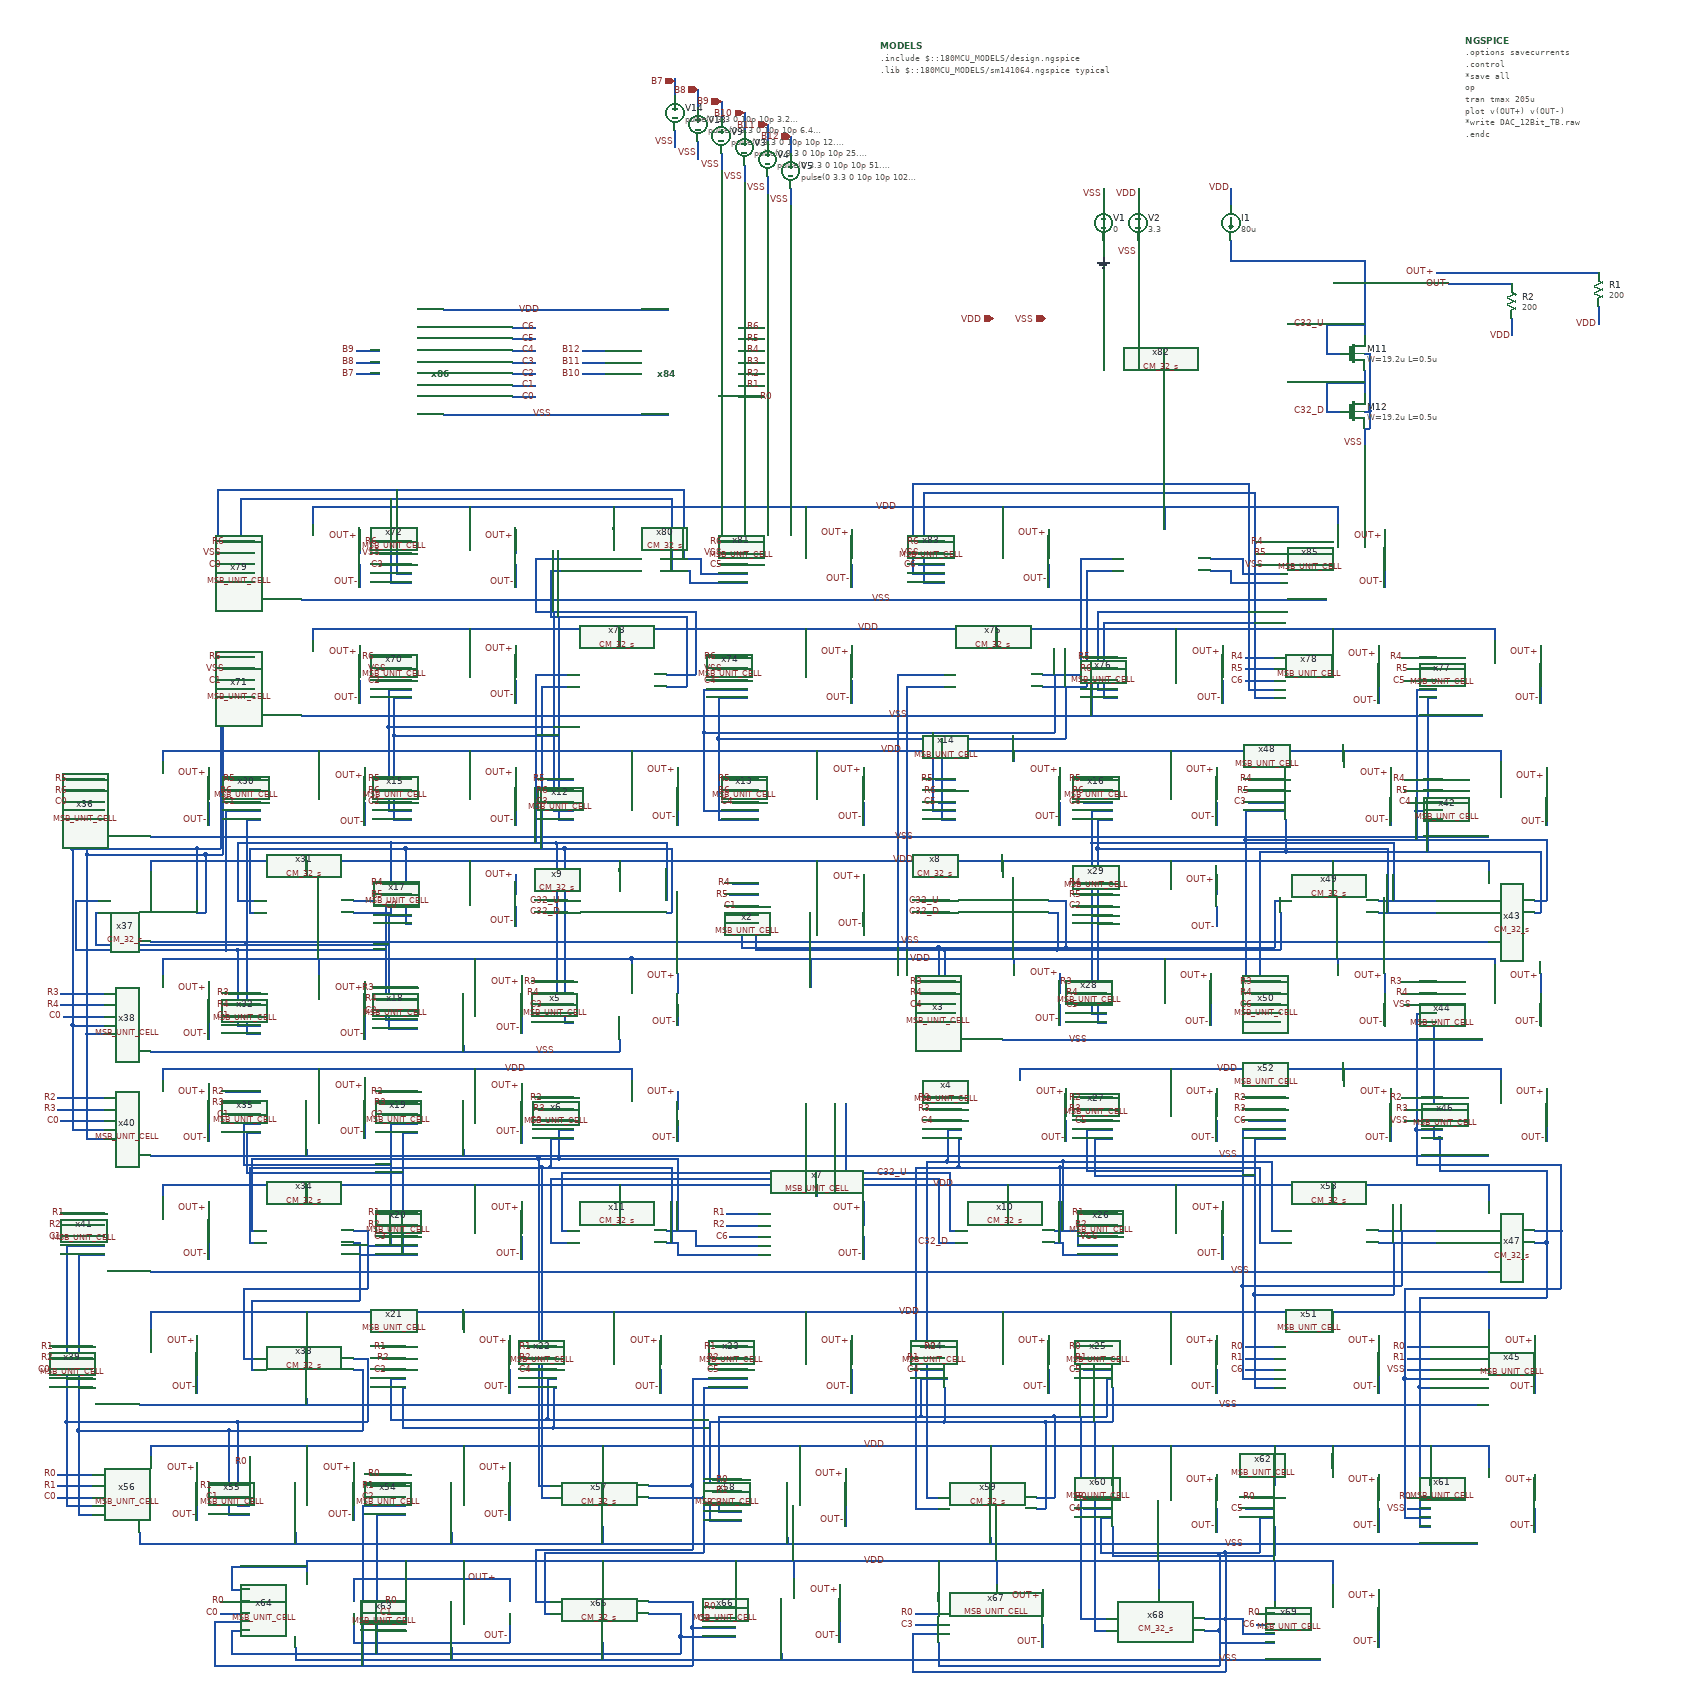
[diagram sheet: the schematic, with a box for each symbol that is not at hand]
v {xschem version=3.1.0 file_version=1.2
}
G {}
K {}
V {}
S {}
E {}
N 2280 -1190 3110 -1190 {
lab=VSS}
N 2280 -1360 3120 -1360 {
lab=VSS}
N 2280 -1540 3120 -1540 {
lab=VSS}
N 810 -1540 2280 -1540 {
lab=VSS}
N 1070 -1750 3110 -1750 {
lab=VSS}
N 1070 -1950 1900 -1950 {
lab=VSS}
N 1900 -1950 2840 -1950 {
lab=VSS}
N 1620 -1360 2280 -1360 {
lab=VSS}
N 820 -1360 1620 -1360 {
lab=VSS}
N 810 -1360 820 -1360 {
lab=VSS}
N 1060 -140 1060 -120 {
lab=VSS}
N 1060 -120 2810 -120 {
lab=VSS}
N 2810 -120 2830 -120 {
lab=VSS}
N 1330 -140 1330 -120 {
lab=VSS}
N 1590 -150 1590 -120 {
lab=VSS}
N 1900 -130 1900 -120 {
lab=VSS}
N 790 -340 790 -320 {
lab=VSS}
N 790 -320 3100 -320 {
lab=VSS}
N 1060 -340 1060 -320 {
lab=VSS}
N 1330 -340 1330 -320 {
lab=VSS}
N 1590 -350 1590 -320 {
lab=VSS}
N 1910 -330 1910 -320 {
lab=VSS}
N 2260 -330 2260 -320 {
lab=VSS}
N 790 -560 3100 -560 {
lab=VSS}
N 810 -790 3120 -790 {
lab=VSS}
N 810 -990 3120 -990 {
lab=VSS}
N 1080 -1000 1080 -990 {
lab=VSS}
N 1940 -1080 1940 -990 {
lab=VSS}
N 810 -1170 1620 -1170 {
lab=VSS}
N 1620 -1190 1620 -1170 {
lab=VSS}
N 1350 -1180 1350 -1170 {
lab=VSS}
N 1090 -2110 1090 -2080 {
lab=VDD}
N 1090 -2110 2860 -2110 {
lab=VDD}
N 2860 -2110 2860 -2080 {
lab=VDD}
N 1090 -1890 1090 -1880 {
lab=VDD}
N 1090 -1900 1090 -1890 {
lab=VDD}
N 1090 -1900 3130 -1900 {
lab=VDD}
N 3130 -1900 3130 -1880 {
lab=VDD}
N 1360 -2110 1360 -2080 {
lab=VDD}
N 1610 -2110 1610 -2070 {
lab=VDD}
N 1940 -2110 1940 -2080 {
lab=VDD}
N 2280 -2110 2280 -2080 {
lab=VDD}
N 2560 -2110 2560 -2070 {
lab=VDD}
N 2850 -1900 2850 -1880 {
lab=VDD}
N 2580 -1900 2580 -1880 {
lab=VDD}
N 2270 -1900 2270 -1870 {
lab=VDD}
N 1940 -1900 1940 -1880 {
lab=VDD}
N 1620 -1900 1620 -1870 {
lab=VDD}
N 1360 -1900 1360 -1880 {
lab=VDD}
N 830 -1690 830 -1670 {
lab=VDD}
N 830 -1690 3140 -1690 {
lab=VDD}
N 3140 -1690 3140 -1670 {
lab=VDD}
N 1100 -1690 1100 -1670 {
lab=VDD}
N 1360 -1690 1360 -1670 {
lab=VDD}
N 1640 -1690 1640 -1670 {
lab=VDD}
N 1960 -1690 1960 -1670 {
lab=VDD}
N 2300 -1690 2300 -1670 {
lab=VDD}
N 2570 -1690 2570 -1670 {
lab=VDD}
N 2870 -1690 2870 -1670 {
lab=VDD}
N 810 -1500 810 -1480 {
lab=VDD}
N 810 -1500 3120 -1500 {
lab=VDD}
N 3120 -1500 3120 -1480 {
lab=VDD}
N 2850 -1500 2850 -1480 {
lab=VDD}
N 2570 -1500 2570 -1490 {
lab=VDD}
N 1960 -1500 1960 -1490 {
lab=VDD}
N 2280 -1500 2280 -1480 {
lab=VDD}
N 1620 -1500 1620 -1480 {
lab=VDD}
N 1360 -1500 1360 -1490 {
lab=VDD}
N 1080 -1500 1080 -1480 {
lab=VDD}
N 830 -1310 830 -1300 {
lab=VDD}
N 830 -1320 830 -1310 {
lab=VDD}
N 830 -1330 830 -1320 {
lab=VDD}
N 830 -1330 1640 -1330 {
lab=VDD}
N 1640 -1330 1640 -1320 {
lab=VDD}
N 1640 -1330 3130 -1330 {
lab=VDD}
N 3130 -1330 3130 -1320 {
lab=VDD}
N 2860 -1330 2860 -1320 {
lab=VDD}
N 2560 -1330 2560 -1320 {
lab=VDD}
N 2300 -1330 2300 -1320 {
lab=VDD}
N 1350 -1000 1350 -990 {
lab=VSS}
N 830 -1140 830 -1120 {
lab=VDD}
N 830 -1140 1640 -1140 {
lab=VDD}
N 1640 -1140 1640 -1120 {
lab=VDD}
N 1370 -1140 1370 -1130 {
lab=VDD}
N 2310 -1140 2310 -1120 {
lab=VDD}
N 2310 -1140 3140 -1140 {
lab=VDD}
N 3140 -1140 3140 -1120 {
lab=VDD}
N 2570 -1140 2570 -1120 {
lab=VDD}
N 2870 -1130 2870 -1120 {
lab=VDD}
N 2870 -1140 2870 -1130 {
lab=VDD}
N 830 -940 830 -920 {
lab=VDD}
N 830 -940 3120 -940 {
lab=VDD}
N 3120 -940 3120 -910 {
lab=VDD}
N 2850 -940 2850 -910 {
lab=VDD}
N 2580 -940 2580 -920 {
lab=VDD}
N 2290 -940 2290 -910 {
lab=VDD}
N 1960 -940 1960 -920 {
lab=VDD}
N 1620 -940 1620 -910 {
lab=VDD}
N 1370 -940 1370 -920 {
lab=VDD}
N 1080 -940 1080 -910 {
lab=VDD}
N 810 -720 810 -690 {
lab=VDD}
N 810 -720 3120 -720 {
lab=VDD}
N 3120 -720 3120 -690 {
lab=VDD}
N 2850 -720 2850 -690 {
lab=VDD}
N 2570 -720 2570 -690 {
lab=VDD}
N 2280 -720 2280 -690 {
lab=VDD}
N 1940 -720 1940 -690 {
lab=VDD}
N 1610 -720 1610 -690 {
lab=VDD}
N 1350 -720 1350 -690 {
lab=VDD}
N 1080 -720 1080 -690 {
lab=VDD}
N 810 -490 810 -470 {
lab=VDD}
N 810 -490 3120 -490 {
lab=VDD}
N 3120 -490 3120 -450 {
lab=VDD}
N 1080 -290 1080 -270 {
lab=VDD}
N 1080 -290 2850 -290 {
lab=VDD}
N 2850 -290 2850 -250 {
lab=VDD}
N 2550 -290 2550 -240 {
lab=VDD}
N 2270 -290 2270 -250 {
lab=VDD}
N 1920 -290 1920 -260 {
lab=VDD}
N 1590 -290 1590 -270 {
lab=VDD}
N 1350 -290 1350 -270 {
lab=VDD}
N 1100 -1330 1100 -1300 {
lab=VDD}
N 1370 -1330 1370 -1310 {
lab=VDD}
N 1950 -1330 1950 -1280 {
lab=VDD}
N 1080 -490 1080 -470 {
lab=VDD}
N 1350 -490 1350 -470 {
lab=VDD}
N 1590 -490 1590 -470 {
lab=VDD}
N 1930 -490 1930 -460 {
lab=VDD}
N 2260 -490 2260 -450 {
lab=VDD}
N 2570 -490 2570 -450 {
lab=VDD}
N 2850 -490 2850 -450 {
lab=VDD}
N 2010 -1080 2010 -960 {
lab=C32_U}
N 2010 -960 2190 -960 {
lab=C32_U}
N 2190 -960 2190 -860 {
lab=C32_U}
N 2190 -860 2200 -860 {
lab=C32_U}
N 1990 -1080 1990 -950 {
lab=C32_D}
N 1990 -950 2170 -950 {
lab=C32_D}
N 2170 -950 2170 -840 {
lab=C32_D}
N 2170 -840 2200 -840 {
lab=C32_D}
N 1520 -960 2010 -960 {
lab=C32_U}
N 1520 -960 1520 -860 {
lab=C32_U}
N 1520 -860 1530 -860 {
lab=C32_U}
N 1500 -950 1990 -950 {
lab=C32_D}
N 1500 -950 1500 -840 {
lab=C32_D}
N 1500 -840 1530 -840 {
lab=C32_D}
N 2370 -860 2410 -860 {
lab=#net1}
N 2410 -860 2410 -835 {
lab=#net1}
N 2410 -835 2480 -835 {
lab=#net1}
N 2370 -840 2385 -840 {
lab=#net2}
N 2385 -840 2385 -820 {
lab=#net2}
N 2385 -820 2480 -820 {
lab=#net2}
N 2385 -965 2385 -860 {
lab=#net1}
N 2385 -980 2385 -965 {
lab=#net1}
N 2185 -980 2385 -980 {
lab=#net1}
N 2185 -1035 2185 -980 {
lab=#net1}
N 2185 -1035 2210 -1035 {
lab=#net1}
N 2380 -960 2380 -840 {
lab=#net2}
N 2380 -970 2380 -960 {
lab=#net2}
N 2205 -970 2380 -970 {
lab=#net2}
N 2205 -1020 2205 -970 {
lab=#net2}
N 2205 -1020 2210 -1020 {
lab=#net2}
N 2385 -980 2745 -980 {
lab=#net1}
N 2745 -980 2745 -860 {
lab=#net1}
N 2745 -860 2760 -860 {
lab=#net1}
N 2380 -970 2725 -970 {
lab=#net2}
N 2725 -970 2725 -840 {
lab=#net2}
N 2725 -840 2760 -840 {
lab=#net2}
N 2150 -980 2185 -980 {
lab=#net1}
N 2150 -980 2150 -400 {
lab=#net1}
N 2150 -400 2170 -400 {
lab=#net1}
N 2130 -970 2205 -970 {
lab=#net2}
N 2130 -970 2130 -390 {
lab=#net2}
N 2130 -390 2130 -380 {
lab=#net2}
N 2130 -380 2170 -380 {
lab=#net2}
N 1700 -860 1750 -860 {
lab=#net3}
N 1750 -860 1750 -835 {
lab=#net3}
N 1750 -835 1860 -835 {
lab=#net3}
N 1700 -840 1720 -840 {
lab=#net4}
N 1720 -840 1720 -820 {
lab=#net4}
N 1720 -820 1855 -820 {
lab=#net4}
N 1855 -820 1860 -820 {
lab=#net4}
N 1720 -985 1720 -860 {
lab=#net3}
N 1515 -985 1720 -985 {
lab=#net3}
N 1515 -1035 1515 -985 {
lab=#net3}
N 1515 -1035 1540 -1035 {
lab=#net3}
N 1710 -970 1710 -840 {
lab=#net4}
N 1500 -970 1710 -970 {
lab=#net4}
N 1500 -1020 1500 -970 {
lab=#net4}
N 1500 -1020 1540 -1020 {
lab=#net4}
N 1480 -985 1515 -985 {
lab=#net3}
N 1480 -985 1480 -420 {
lab=#net3}
N 1480 -420 1500 -420 {
lab=#net3}
N 1485 -970 1500 -970 {
lab=#net4}
N 1485 -970 1485 -400 {
lab=#net4}
N 1485 -400 1500 -400 {
lab=#net4}
N 985 -985 1480 -985 {
lab=#net3}
N 985 -985 985 -860 {
lab=#net3}
N 985 -860 990 -860 {
lab=#net3}
N 980 -970 1485 -970 {
lab=#net4}
N 980 -970 980 -840 {
lab=#net4}
N 980 -840 990 -840 {
lab=#net4}
N 2140 -1430 2190 -1430 {
lab=C32_U}
N 2140 -1410 2190 -1410 {
lab=C32_D}
N 1495 -1430 1530 -1430 {
lab=C32_U}
N 1495 -1410 1530 -1410 {
lab=C32_D}
N 2360 -1430 2390 -1430 {
lab=#net5}
N 2390 -1430 2390 -1350 {
lab=#net5}
N 2170 -1350 2390 -1350 {
lab=#net5}
N 2170 -1350 2170 -1235 {
lab=#net5}
N 2170 -1235 2200 -1235 {
lab=#net5}
N 2360 -1410 2375 -1410 {
lab=#net6}
N 2375 -1410 2375 -1345 {
lab=#net6}
N 2180 -1345 2375 -1345 {
lab=#net6}
N 2180 -1345 2180 -1220 {
lab=#net6}
N 2180 -1220 2200 -1220 {
lab=#net6}
N 1830 -1350 2170 -1350 {
lab=#net5}
N 1830 -1405 1830 -1350 {
lab=#net5}
N 1830 -1405 1860 -1405 {
lab=#net5}
N 1855 -1345 2180 -1345 {
lab=#net6}
N 1855 -1390 1855 -1345 {
lab=#net6}
N 1855 -1390 1860 -1390 {
lab=#net6}
N 2390 -1350 2750 -1350 {
lab=#net5}
N 2750 -1430 2750 -1350 {
lab=#net5}
N 2750 -1430 2760 -1430 {
lab=#net5}
N 2375 -1345 2760 -1345 {
lab=#net6}
N 2760 -1410 2760 -1345 {
lab=#net6}
N 2100 -1820 2100 -1350 {
lab=#net5}
N 2100 -1820 2180 -1820 {
lab=#net5}
N 2115 -1800 2115 -1345 {
lab=#net6}
N 2115 -1800 2180 -1800 {
lab=#net6}
N 1700 -1530 1700 -1430 {
lab=#net7}
N 1510 -1530 1700 -1530 {
lab=#net7}
N 1700 -1410 1710 -1410 {
lab=#net8}
N 1710 -1520 1710 -1410 {
lab=#net8}
N 1525 -1520 1710 -1520 {
lab=#net8}
N 1510 -1530 1510 -1235 {
lab=#net7}
N 1510 -1235 1540 -1235 {
lab=#net7}
N 1525 -1520 1525 -1220 {
lab=#net8}
N 1525 -1220 1540 -1220 {
lab=#net8}
N 1225 -1530 1510 -1530 {
lab=#net7}
N 1225 -1530 1225 -1405 {
lab=#net7}
N 1225 -1405 1260 -1405 {
lab=#net7}
N 1250 -1520 1525 -1520 {
lab=#net8}
N 1250 -1520 1250 -1390 {
lab=#net8}
N 1250 -1390 1260 -1390 {
lab=#net8}
N 960 -1530 1225 -1530 {
lab=#net7}
N 960 -1530 960 -1430 {
lab=#net7}
N 960 -1430 990 -1430 {
lab=#net7}
N 980 -1520 1250 -1520 {
lab=#net8}
N 980 -1520 980 -1410 {
lab=#net8}
N 980 -1410 990 -1410 {
lab=#net8}
N 1160 -1430 1200 -1430 {
lab=#net9}
N 1200 -1430 1205 -1430 {
lab=#net9}
N 1205 -1430 1215 -1430 {
lab=#net9}
N 1215 -1430 1215 -1225 {
lab=#net9}
N 1215 -1225 1270 -1225 {
lab=#net9}
N 1160 -1410 1220 -1410 {
lab=#net10}
N 1220 -1410 1220 -1210 {
lab=#net10}
N 1220 -1210 1270 -1210 {
lab=#net10}
N 960 -1345 1215 -1345 {
lab=#net9}
N 960 -1345 960 -1215 {
lab=#net9}
N 960 -1215 1000 -1215 {
lab=#net9}
N 975 -1355 1220 -1355 {
lab=#net10}
N 975 -1355 975 -1200 {
lab=#net10}
N 975 -1200 1000 -1200 {
lab=#net10}
N 975 -1570 975 -1355 {
lab=#net10}
N 975 -1570 1000 -1570 {
lab=#net10}
N 940 -1345 960 -1345 {
lab=#net9}
N 940 -1585 940 -1345 {
lab=#net9}
N 940 -1585 1000 -1585 {
lab=#net9}
N 715 -1355 975 -1355 {
lab=#net10}
N 715 -1410 715 -1355 {
lab=#net10}
N 715 -1410 720 -1410 {
lab=#net10}
N 680 -1345 940 -1345 {
lab=#net9}
N 680 -1430 680 -1345 {
lab=#net9}
N 680 -1430 720 -1430 {
lab=#net9}
N 1100 -1140 1100 -1130 {
lab=VDD}
N 1080 -570 1080 -560 {
lab=VSS}
N 1160 -860 1185 -860 {
lab=#net11}
N 1185 -860 1185 -760 {
lab=#net11}
N 970 -760 1185 -760 {
lab=#net11}
N 970 -760 970 -645 {
lab=#net11}
N 970 -645 970 -640 {
lab=#net11}
N 970 -640 990 -640 {
lab=#net11}
N 1160 -840 1170 -840 {
lab=#net12}
N 1170 -840 1170 -740 {
lab=#net12}
N 985 -740 1170 -740 {
lab=#net12}
N 985 -740 985 -620 {
lab=#net12}
N 985 -620 990 -620 {
lab=#net12}
N 1185 -835 1270 -835 {
lab=#net11}
N 1170 -820 1270 -820 {
lab=#net12}
N 1225 -1045 1225 -835 {
lab=#net11}
N 1225 -1045 1270 -1045 {
lab=#net11}
N 1245 -1030 1245 -820 {
lab=#net12}
N 1245 -1030 1270 -1030 {
lab=#net12}
N 970 -975 1225 -975 {
lab=#net11}
N 970 -1045 970 -975 {
lab=#net11}
N 970 -1045 1000 -1045 {
lab=#net11}
N 975 -960 1245 -960 {
lab=#net12}
N 975 -1030 975 -960 {
lab=#net12}
N 975 -1030 1000 -1030 {
lab=#net12}
N 1160 -640 1185 -640 {
lab=#net13}
N 1185 -640 1185 -530 {
lab=#net13}
N 960 -530 1185 -530 {
lab=#net13}
N 960 -530 960 -385 {
lab=#net13}
N 960 -385 980 -385 {
lab=#net13}
N 1160 -620 1175 -620 {
lab=#net14}
N 1175 -620 1175 -515 {
lab=#net14}
N 975 -515 1175 -515 {
lab=#net14}
N 945 -515 975 -515 {
lab=#net14}
N 945 -515 945 -370 {
lab=#net14}
N 945 -370 980 -370 {
lab=#net14}
N 665 -530 960 -530 {
lab=#net13}
N 665 -530 665 -385 {
lab=#net13}
N 665 -385 710 -385 {
lab=#net13}
N 685 -515 945 -515 {
lab=#net14}
N 685 -515 685 -370 {
lab=#net14}
N 685 -370 710 -370 {
lab=#net14}
N 665 -830 665 -530 {
lab=#net13}
N 665 -835 665 -830 {
lab=#net13}
N 665 -835 730 -835 {
lab=#net13}
N 685 -820 685 -515 {
lab=#net14}
N 685 -820 730 -820 {
lab=#net14}
N 665 -605 710 -605 {
lab=#net13}
N 685 -590 710 -590 {
lab=#net14}
N 1670 -420 1745 -420 {
lab=#net15}
N 1745 -605 1745 -420 {
lab=#net15}
N 1745 -605 1840 -605 {
lab=#net15}
N 1670 -400 1765 -400 {
lab=#net16}
N 1765 -590 1765 -400 {
lab=#net16}
N 1765 -590 1840 -590 {
lab=#net16}
N 1495 -535 1745 -535 {
lab=#net15}
N 1495 -605 1495 -535 {
lab=#net15}
N 1495 -605 1505 -605 {
lab=#net15}
N 1505 -520 1765 -520 {
lab=#net16}
N 1505 -590 1505 -520 {
lab=#net16}
N 1505 -590 1510 -590 {
lab=#net16}
N 1225 -535 1495 -535 {
lab=#net15}
N 1225 -605 1225 -535 {
lab=#net15}
N 1225 -605 1250 -605 {
lab=#net15}
N 1245 -520 1505 -520 {
lab=#net16}
N 1245 -590 1245 -520 {
lab=#net16}
N 1245 -590 1250 -590 {
lab=#net16}
N 1745 -420 1745 -310 {
lab=#net15}
N 1485 -220 1500 -220 {
lab=#net15}
N 1495 -200 1500 -200 {
lab=#net16}
N 1490 -200 1495 -200 {
lab=#net16}
N 1490 -305 1490 -200 {
lab=#net16}
N 1765 -400 1765 -305 {
lab=#net16}
N 1490 -305 1765 -305 {
lab=#net16}
N 1475 -310 1745 -310 {
lab=#net15}
N 1475 -310 1475 -220 {
lab=#net15}
N 1475 -220 1485 -220 {
lab=#net15}
N 2340 -400 2370 -400 {
lab=#net17}
N 2370 -540 2370 -400 {
lab=#net17}
N 2140 -540 2370 -540 {
lab=#net17}
N 2140 -605 2140 -540 {
lab=#net17}
N 2140 -605 2185 -605 {
lab=#net17}
N 2340 -380 2355 -380 {
lab=#net18}
N 2355 -530 2355 -380 {
lab=#net18}
N 2180 -530 2355 -530 {
lab=#net18}
N 2180 -590 2180 -530 {
lab=#net18}
N 2355 -530 2470 -530 {
lab=#net18}
N 2470 -590 2470 -530 {
lab=#net18}
N 2370 -540 2460 -540 {
lab=#net17}
N 2460 -605 2460 -540 {
lab=#net17}
N 2460 -605 2470 -605 {
lab=#net17}
N 1790 -540 2140 -540 {
lab=#net17}
N 1790 -540 1790 -375 {
lab=#net17}
N 1790 -375 1830 -375 {
lab=#net17}
N 1775 -530 2180 -530 {
lab=#net18}
N 1775 -530 1775 -360 {
lab=#net18}
N 1775 -360 1830 -360 {
lab=#net18}
N 2415 -540 2415 -190 {
lab=#net17}
N 2415 -190 2460 -190 {
lab=#net17}
N 2440 -530 2440 -170 {
lab=#net18}
N 2440 -170 2460 -170 {
lab=#net18}
N 2930 -860 3030 -860 {
lab=#net19}
N 2930 -840 3030 -840 {
lab=#net20}
N 2970 -860 2970 -765 {
lab=#net19}
N 2695 -765 2970 -765 {
lab=#net19}
N 2695 -765 2695 -605 {
lab=#net19}
N 2695 -605 2750 -605 {
lab=#net19}
N 2955 -840 2955 -750 {
lab=#net20}
N 2715 -750 2955 -750 {
lab=#net20}
N 2715 -750 2715 -590 {
lab=#net20}
N 2715 -590 2750 -590 {
lab=#net20}
N 2695 -1035 2695 -765 {
lab=#net19}
N 2695 -1035 2770 -1035 {
lab=#net19}
N 2715 -1020 2715 -750 {
lab=#net20}
N 2715 -1020 2770 -1020 {
lab=#net20}
N 2425 -965 2695 -965 {
lab=#net19}
N 2425 -1035 2425 -965 {
lab=#net19}
N 2425 -1035 2470 -1035 {
lab=#net19}
N 2440 -955 2715 -955 {
lab=#net20}
N 2440 -1020 2440 -955 {
lab=#net20}
N 2440 -1020 2470 -1020 {
lab=#net20}
N 2930 -1430 3030 -1430 {
lab=#net21}
N 2930 -1410 3030 -1410 {
lab=#net22}
N 2955 -1530 2955 -1430 {
lab=#net21}
N 2435 -1530 2955 -1530 {
lab=#net21}
N 2435 -1585 2435 -1530 {
lab=#net21}
N 2435 -1585 2465 -1585 {
lab=#net21}
N 2465 -1585 2470 -1585 {
lab=#net21}
N 2945 -1520 2945 -1410 {
lab=#net22}
N 2445 -1520 2945 -1520 {
lab=#net22}
N 2445 -1570 2445 -1520 {
lab=#net22}
N 2445 -1570 2470 -1570 {
lab=#net22}
N 2435 -1530 2435 -1235 {
lab=#net21}
N 2435 -1235 2460 -1235 {
lab=#net21}
N 2445 -1520 2445 -1220 {
lab=#net22}
N 2445 -1220 2460 -1220 {
lab=#net22}
N 2435 -1405 2470 -1405 {
lab=#net21}
N 2445 -1390 2470 -1390 {
lab=#net22}
N 2350 -1820 2415 -1820 {
lab=#net23}
N 2415 -2020 2415 -1820 {
lab=#net23}
N 2415 -2020 2470 -2020 {
lab=#net23}
N 2350 -1800 2425 -1800 {
lab=#net24}
N 2425 -2000 2425 -1800 {
lab=#net24}
N 2425 -2000 2470 -2000 {
lab=#net24}
N 2370 -1820 2370 -1720 {
lab=#net23}
N 1765 -1720 2370 -1720 {
lab=#net23}
N 1765 -1720 1765 -1585 {
lab=#net23}
N 1765 -1585 1860 -1585 {
lab=#net23}
N 2390 -1800 2390 -1710 {
lab=#net24}
N 1790 -1710 2390 -1710 {
lab=#net24}
N 1790 -1710 1790 -1575 {
lab=#net24}
N 1790 -1575 1790 -1570 {
lab=#net24}
N 1790 -1570 1860 -1570 {
lab=#net24}
N 2160 -1720 2160 -1585 {
lab=#net23}
N 2160 -1585 2200 -1585 {
lab=#net23}
N 2175 -1710 2175 -1570 {
lab=#net24}
N 2175 -1570 2200 -1570 {
lab=#net24}
N 1765 -1790 1765 -1720 {
lab=#net23}
N 1765 -1795 1765 -1790 {
lab=#net23}
N 1765 -1795 1840 -1795 {
lab=#net23}
N 1790 -1780 1790 -1710 {
lab=#net24}
N 1790 -1780 1840 -1780 {
lab=#net24}
N 1510 -1820 1530 -1820 {
lab=#net7}
N 1525 -1800 1530 -1800 {
lab=#net8}
N 1475 -1820 1475 -1530 {
lab=#net7}
N 1475 -1820 1510 -1820 {
lab=#net7}
N 1485 -1800 1485 -1520 {
lab=#net8}
N 1485 -1800 1525 -1800 {
lab=#net8}
N 1700 -1820 1750 -1820 {
lab=#net25}
N 1750 -1930 1750 -1820 {
lab=#net25}
N 1475 -1930 1750 -1930 {
lab=#net25}
N 1475 -2020 1475 -1930 {
lab=#net25}
N 1475 -2020 1520 -2020 {
lab=#net25}
N 1700 -1800 1735 -1800 {
lab=#net26}
N 1735 -1920 1735 -1800 {
lab=#net26}
N 1500 -1920 1735 -1920 {
lab=#net26}
N 1500 -2000 1500 -1920 {
lab=#net26}
N 1500 -2000 1520 -2000 {
lab=#net26}
N 1505 -1585 1540 -1585 {
lab=#net25}
N 1505 -1930 1505 -1585 {
lab=#net25}
N 1515 -1920 1515 -1570 {
lab=#net26}
N 1515 -1570 1540 -1570 {
lab=#net26}
N 1220 -1730 1505 -1730 {
lab=#net25}
N 1220 -1730 1220 -1585 {
lab=#net25}
N 1220 -1585 1260 -1585 {
lab=#net25}
N 1230 -1715 1515 -1715 {
lab=#net26}
N 1230 -1715 1230 -1575 {
lab=#net26}
N 1230 -1575 1230 -1570 {
lab=#net26}
N 1230 -1570 1260 -1570 {
lab=#net26}
N 1220 -1795 1220 -1730 {
lab=#net25}
N 1220 -1795 1260 -1795 {
lab=#net25}
N 1230 -1780 1260 -1780 {
lab=#net26}
N 1230 -1780 1230 -1715 {
lab=#net26}
N 890 -1520 890 -1430 {
lab=#net27}
N 675 -1520 890 -1520 {
lab=#net27}
N 675 -1585 675 -1520 {
lab=#net27}
N 675 -1585 730 -1585 {
lab=#net27}
N 890 -1410 905 -1410 {
lab=#net28}
N 905 -1510 905 -1410 {
lab=#net28}
N 700 -1510 905 -1510 {
lab=#net28}
N 700 -1570 700 -1510 {
lab=#net28}
N 700 -1570 730 -1570 {
lab=#net28}
N 675 -1520 675 -1215 {
lab=#net27}
N 675 -1215 730 -1215 {
lab=#net27}
N 700 -1510 700 -1200 {
lab=#net28}
N 700 -1200 730 -1200 {
lab=#net28}
N 890 -1520 925 -1520 {
lab=#net27}
N 925 -1520 930 -1520 {
lab=#net27}
N 930 -1790 930 -1520 {
lab=#net27}
N 930 -1795 930 -1790 {
lab=#net27}
N 930 -1795 990 -1795 {
lab=#net27}
N 905 -1510 920 -1510 {
lab=#net28}
N 920 -1510 935 -1510 {
lab=#net28}
N 935 -1780 935 -1510 {
lab=#net28}
N 935 -1780 990 -1780 {
lab=#net28}
N 700 -1200 700 -1020 {
lab=#net28}
N 700 -1020 730 -1020 {
lab=#net28}
N 675 -1215 675 -1035 {
lab=#net27}
N 675 -1035 730 -1035 {
lab=#net27}
N 1670 -220 1745 -220 {
lab=#net29}
N 1745 -220 1745 -175 {
lab=#net29}
N 1745 -175 1820 -175 {
lab=#net29}
N 1670 -200 1725 -200 {
lab=#net30}
N 1725 -200 1725 -160 {
lab=#net30}
N 1725 -160 1820 -160 {
lab=#net30}
N 1745 -175 1745 -110 {
lab=#net29}
N 925 -110 1745 -110 {
lab=#net29}
N 920 -185 980 -185 {
lab=#net29}
N 920 -185 920 -110 {
lab=#net29}
N 920 -110 925 -110 {
lab=#net29}
N 1725 -160 1725 -130 {
lab=#net30}
N 950 -130 1725 -130 {
lab=#net30}
N 950 -170 950 -130 {
lab=#net30}
N 950 -170 980 -170 {
lab=#net30}
N 1175 -385 1175 -110 {
lab=#net29}
N 1175 -385 1250 -385 {
lab=#net29}
N 1200 -370 1200 -130 {
lab=#net30}
N 1200 -370 1250 -370 {
lab=#net30}
N 1200 -170 1250 -170 {
lab=#net30}
N 1175 -185 1250 -185 {
lab=#net29}
N 2630 -190 2665 -190 {
lab=#net31}
N 2665 -305 2665 -190 {
lab=#net31}
N 2450 -305 2665 -305 {
lab=#net31}
N 2450 -365 2450 -305 {
lab=#net31}
N 2450 -365 2470 -365 {
lab=#net31}
N 2470 -350 2470 -300 {
lab=#net32}
N 2470 -300 2655 -300 {
lab=#net32}
N 2655 -300 2655 -170 {
lab=#net32}
N 2630 -170 2655 -170 {
lab=#net32}
N 2665 -190 2695 -190 {
lab=#net31}
N 2695 -190 2695 -165 {
lab=#net31}
N 2695 -165 2750 -165 {
lab=#net31}
N 2655 -170 2655 -150 {
lab=#net32}
N 2655 -150 2750 -150 {
lab=#net32}
N 2665 -305 2725 -305 {
lab=#net31}
N 2725 -365 2725 -305 {
lab=#net31}
N 2725 -365 2750 -365 {
lab=#net31}
N 2655 -300 2750 -300 {
lab=#net32}
N 2750 -350 2750 -300 {
lab=#net32}
N 2665 -190 2665 -100 {
lab=#net31}
N 2125 -100 2665 -100 {
lab=#net31}
N 2125 -165 2125 -100 {
lab=#net31}
N 2125 -165 2170 -165 {
lab=#net31}
N 2655 -170 2655 -110 {
lab=#net32}
N 2170 -110 2655 -110 {
lab=#net32}
N 2170 -150 2170 -110 {
lab=#net32}
N 3200 -860 3245 -860 {
lab=#net33}
N 3245 -860 3245 -760 {
lab=#net33}
N 2995 -760 3245 -760 {
lab=#net33}
N 2975 -760 2995 -760 {
lab=#net33}
N 2975 -760 2975 -605 {
lab=#net33}
N 2975 -605 3020 -605 {
lab=#net33}
N 3200 -840 3220 -840 {
lab=#net34}
N 3220 -840 3220 -745 {
lab=#net34}
N 3000 -745 3220 -745 {
lab=#net34}
N 3000 -745 3000 -590 {
lab=#net34}
N 3000 -590 3020 -590 {
lab=#net34}
N 2975 -605 2975 -365 {
lab=#net33}
N 2975 -365 3020 -365 {
lab=#net33}
N 3000 -590 3000 -350 {
lab=#net34}
N 3000 -350 3020 -350 {
lab=#net34}
N 3245 -975 3245 -860 {
lab=#net33}
N 2995 -975 3245 -975 {
lab=#net33}
N 2995 -1035 2995 -975 {
lab=#net33}
N 2995 -1035 3040 -1035 {
lab=#net33}
N 3220 -965 3220 -840 {
lab=#net34}
N 3035 -965 3220 -965 {
lab=#net34}
N 3035 -1020 3035 -965 {
lab=#net34}
N 3035 -1020 3040 -1020 {
lab=#net34}
N 2995 -1235 2995 -1035 {
lab=#net33}
N 2995 -1235 3030 -1235 {
lab=#net33}
N 3025 -1020 3035 -1020 {
lab=#net34}
N 3025 -1220 3025 -1020 {
lab=#net34}
N 3025 -1220 3030 -1220 {
lab=#net34}
N 3200 -1430 3220 -1430 {
lab=#net35}
N 3220 -1520 3220 -1430 {
lab=#net35}
N 3220 -1535 3220 -1520 {
lab=#net35}
N 2700 -1535 3220 -1535 {
lab=#net35}
N 2700 -1585 2700 -1535 {
lab=#net35}
N 2700 -1585 2770 -1585 {
lab=#net35}
N 3200 -1410 3210 -1410 {
lab=#net36}
N 3210 -1515 3210 -1410 {
lab=#net36}
N 2770 -1515 3210 -1515 {
lab=#net36}
N 2770 -1570 2770 -1515 {
lab=#net36}
N 2995 -1585 2995 -1535 {
lab=#net35}
N 2995 -1585 3040 -1585 {
lab=#net35}
N 3015 -1570 3015 -1515 {
lab=#net36}
N 3015 -1570 3040 -1570 {
lab=#net36}
N 2995 -1795 2995 -1585 {
lab=#net35}
N 2995 -1795 3030 -1795 {
lab=#net35}
N 3015 -1780 3015 -1570 {
lab=#net36}
N 3015 -1780 3030 -1780 {
lab=#net36}
N 2700 -1535 2700 -1235 {
lab=#net35}
N 2700 -1235 2760 -1235 {
lab=#net35}
N 2725 -1515 2770 -1515 {
lab=#net36}
N 2725 -1515 2725 -1220 {
lab=#net36}
N 2725 -1220 2760 -1220 {
lab=#net36}
N 2640 -2020 2685 -2020 {
lab=#net37}
N 2685 -2020 2695 -2020 {
lab=#net37}
N 2695 -2020 2695 -1995 {
lab=#net37}
N 2695 -1995 2760 -1995 {
lab=#net37}
N 2640 -2000 2675 -2000 {
lab=#net38}
N 2675 -2000 2675 -1980 {
lab=#net38}
N 2675 -1980 2760 -1980 {
lab=#net38}
N 2705 -1995 2705 -1795 {
lab=#net37}
N 2705 -1795 2750 -1795 {
lab=#net37}
N 2715 -1980 2715 -1780 {
lab=#net38}
N 2715 -1780 2750 -1780 {
lab=#net38}
N 2445 -1930 2705 -1930 {
lab=#net37}
N 2445 -1930 2445 -1795 {
lab=#net37}
N 2445 -1795 2480 -1795 {
lab=#net37}
N 2455 -1910 2715 -1910 {
lab=#net38}
N 2455 -1910 2455 -1780 {
lab=#net38}
N 2455 -1780 2480 -1780 {
lab=#net38}
N 2705 -2150 2705 -2000 {
lab=#net37}
N 2125 -2150 2705 -2150 {
lab=#net37}
N 2125 -2150 2125 -1995 {
lab=#net37}
N 2125 -1995 2180 -1995 {
lab=#net37}
N 2715 -2135 2715 -1980 {
lab=#net38}
N 2145 -2135 2715 -2135 {
lab=#net38}
N 2145 -2135 2145 -1980 {
lab=#net38}
N 2145 -1980 2180 -1980 {
lab=#net38}
N 1690 -2020 1760 -2020 {
lab=#net39}
N 1760 -2020 1760 -1995 {
lab=#net39}
N 1760 -1995 1840 -1995 {
lab=#net39}
N 1690 -2000 1740 -2000 {
lab=#net40}
N 1740 -2000 1740 -1980 {
lab=#net40}
N 1740 -1980 1840 -1980 {
lab=#net40}
N 1730 -2140 1730 -2020 {
lab=#net39}
N 955 -2140 1730 -2140 {
lab=#net39}
N 925 -2140 955 -2140 {
lab=#net39}
N 925 -2140 925 -1995 {
lab=#net39}
N 925 -1995 990 -1995 {
lab=#net39}
N 1710 -2125 1710 -2000 {
lab=#net40}
N 965 -2125 1710 -2125 {
lab=#net40}
N 965 -2125 965 -1980 {
lab=#net40}
N 965 -1980 990 -1980 {
lab=#net40}
N 1235 -1995 1260 -1995 {
lab=#net39}
N 1235 -2140 1235 -1995 {
lab=#net39}
N 1225 -2125 1225 -1980 {
lab=#net40}
N 1225 -1980 1260 -1980 {
lab=#net40}
N 950 -240 980 -240 {
lab=VDD}
N 950 -280 950 -240 {
lab=VDD}
N 950 -280 1080 -280 {
lab=VDD}
N 1250 -290 1250 -240 {
lab=VDD}
N 1820 -290 1820 -230 {
lab=VDD}
N 2170 -290 2170 -220 {
lab=VDD}
N 2750 -290 2750 -220 {
lab=VDD}
N 3020 -490 3020 -420 {
lab=VDD}
N 2750 -490 2750 -420 {
lab=VDD}
N 2470 -490 2470 -420 {
lab=VDD}
N 930 -220 980 -220 {
lab=R0}
N 1220 -220 1250 -220 {
lab=R0}
N 2720 -200 2750 -200 {
lab=R0}
N 2990 -400 3020 -400 {
lab=R0}
N 2980 -400 2990 -400 {
lab=R0}
N 2710 -400 2750 -400 {
lab=R0}
N 2420 -400 2470 -400 {
lab=R0}
N 650 -440 710 -440 {
lab=R0}
N 1190 -440 1250 -440 {
lab=R0}
N 1780 -430 1830 -430 {
lab=R0}
N 2140 -660 2180 -660 {
lab=R0}
N 2420 -660 2470 -660 {
lab=R0}
N 2700 -660 2750 -660 {
lab=R0}
N 2980 -660 3020 -660 {
lab=R0}
N 2980 -640 3020 -640 {
lab=R1}
N 2700 -640 2750 -640 {
lab=R1}
N 2420 -640 2470 -640 {
lab=R1}
N 2140 -640 2180 -640 {
lab=R1}
N 650 -420 710 -420 {
lab=R1}
N 920 -420 980 -420 {
lab=R1}
N 1190 -420 1250 -420 {
lab=R1}
N 1780 -410 1830 -410 {
lab=R1}
N 930 -200 980 -200 {
lab=C0}
N 1220 -200 1250 -200 {
lab=C1}
N 1780 -190 1820 -190 {
lab=C2}
N 2130 -180 2170 -180 {
lab=C3}
N 2720 -180 2750 -180 {
lab=C6}
N 2420 -380 2470 -380 {
lab=C4}
N 2700 -380 2750 -380 {
lab=C5}
N 2980 -380 3020 -380 {
lab=VSS}
N 650 -400 710 -400 {
lab=C0}
N 920 -400 980 -400 {
lab=C1}
N 1200 -400 1250 -400 {
lab=C2}
N 1780 -390 1830 -390 {
lab=C3}
N 2140 -620 2180 -620 {
lab=C4}
N 2420 -620 2470 -620 {
lab=C5}
N 2700 -620 2750 -620 {
lab=C6}
N 2980 -620 3020 -620 {
lab=VSS}
N 640 -660 710 -660 {
lab=R1}
N 640 -640 710 -640 {
lab=R2}
N 640 -620 710 -620 {
lab=C0}
N 1210 -660 1250 -660 {
lab=R1}
N 1210 -640 1250 -640 {
lab=R2}
N 1210 -620 1250 -620 {
lab=C2}
N 1460 -660 1510 -660 {
lab=R1}
N 1460 -640 1510 -640 {
lab=R2}
N 1460 -620 1510 -620 {
lab=C4}
N 1505 -605 1510 -605 {
lab=#net15}
N 1785 -660 1840 -660 {
lab=R1}
N 1790 -640 1840 -640 {
lab=R2}
N 1790 -620 1840 -620 {
lab=C5}
N 660 -890 730 -890 {
lab=R1}
N 660 -870 730 -870 {
lab=R2}
N 660 -850 730 -850 {
lab=C1}
N 1205 -890 1270 -890 {
lab=R1}
N 1205 -870 1270 -870 {
lab=R2}
N 1205 -850 1270 -850 {
lab=C3}
N 1805 -890 1860 -890 {
lab=R1}
N 1805 -870 1860 -870 {
lab=R2}
N 1810 -850 1860 -850 {
lab=C6}
N 2420 -890 2480 -890 {
lab=R1}
N 2425 -870 2480 -870 {
lab=R2}
N 2425 -850 2480 -850 {
lab=VSS}
N 650 -1090 730 -1090 {
lab=R2}
N 650 -1070 730 -1070 {
lab=R3}
N 655 -1050 730 -1050 {
lab=C0}
N 940 -1100 1000 -1100 {
lab=R2}
N 940 -1080 1000 -1080 {
lab=R3}
N 945 -1060 1000 -1060 {
lab=C1}
N 1205 -1100 1270 -1100 {
lab=R2}
N 1205 -1080 1270 -1080 {
lab=R3}
N 1210 -1060 1270 -1060 {
lab=C2}
N 1480 -1090 1540 -1090 {
lab=R2}
N 1480 -1070 1540 -1070 {
lab=R3}
N 1485 -1050 1540 -1050 {
lab=C3}
N 2155 -1090 2210 -1090 {
lab=R2}
N 2155 -1070 2210 -1070 {
lab=R3}
N 2160 -1050 2210 -1050 {
lab=C4}
N 2415 -1090 2470 -1090 {
lab=R2}
N 2415 -1070 2470 -1070 {
lab=R3}
N 2415 -1050 2470 -1050 {
lab=C5}
N 2700 -1090 2770 -1090 {
lab=R2}
N 2700 -1070 2770 -1070 {
lab=R3}
N 2705 -1050 2770 -1050 {
lab=C6}
N 2970 -1090 3040 -1090 {
lab=R2}
N 2975 -1070 3040 -1070 {
lab=R3}
N 2975 -1050 3040 -1050 {
lab=VSS}
N 655 -1270 730 -1270 {
lab=R3}
N 655 -1250 730 -1250 {
lab=R4}
N 660 -1230 730 -1230 {
lab=C0}
N 945 -1270 1000 -1270 {
lab=R3}
N 945 -1250 1000 -1250 {
lab=R4}
N 945 -1230 1000 -1230 {
lab=C1}
N 1195 -1280 1270 -1280 {
lab=R3}
N 1200 -1260 1270 -1260 {
lab=R4}
N 1200 -1240 1270 -1240 {
lab=C2}
N 1475 -1290 1540 -1290 {
lab=R3}
N 1480 -1270 1540 -1270 {
lab=R4}
N 1480 -1250 1540 -1250 {
lab=C3}
N 2140 -1290 2200 -1290 {
lab=R3}
N 2140 -1270 2200 -1270 {
lab=R4}
N 2145 -1250 2200 -1250 {
lab=C4}
N 2400 -1290 2460 -1290 {
lab=R3}
N 2405 -1270 2460 -1270 {
lab=R4}
N 2405 -1250 2460 -1250 {
lab=C5}
N 2710 -1290 2760 -1290 {
lab=R3}
N 2710 -1270 2760 -1270 {
lab=R4}
N 2710 -1250 2760 -1250 {
lab=C6}
N 2970 -1290 3030 -1290 {
lab=R3}
N 2970 -1270 3030 -1270 {
lab=R4}
N 2975 -1250 3030 -1250 {
lab=VSS}
N 1210 -1460 1260 -1460 {
lab=R4}
N 1210 -1440 1260 -1440 {
lab=R5}
N 1220 -1420 1260 -1420 {
lab=C0}
N 1815 -1460 1860 -1460 {
lab=R4}
N 1810 -1440 1860 -1440 {
lab=R5}
N 1820 -1420 1860 -1420 {
lab=C1}
N 2415 -1460 2470 -1460 {
lab=R4}
N 2415 -1440 2470 -1440 {
lab=R5}
N 2415 -1420 2470 -1420 {
lab=C2}
N 2705 -1640 2770 -1640 {
lab=R4}
N 2705 -1620 2770 -1620 {
lab=R5}
N 2705 -1600 2770 -1600 {
lab=C3}
N 2975 -1640 3040 -1640 {
lab=R4}
N 2975 -1620 3040 -1620 {
lab=R5}
N 2980 -1600 3040 -1600 {
lab=C4}
N 2700 -1850 2750 -1850 {
lab=R4}
N 2700 -1830 2750 -1830 {
lab=R5}
N 2700 -1810 2750 -1810 {
lab=C6}
N 2970 -1850 3030 -1850 {
lab=R4}
N 2980 -1830 3030 -1830 {
lab=R5}
N 2975 -1810 3030 -1810 {
lab=C5}
N 2720 -2050 2760 -2050 {
lab=R4}
N 2720 -2030 2760 -2030 {
lab=R5}
N 2720 -2010 2760 -2010 {
lab=VSS}
N 665 -1640 730 -1640 {
lab=R5}
N 665 -1620 730 -1620 {
lab=R6}
N 670 -1600 730 -1600 {
lab=C0}
N 950 -1640 1000 -1640 {
lab=R5}
N 950 -1620 1000 -1620 {
lab=R6}
N 950 -1600 1000 -1600 {
lab=C1}
N 1210 -1640 1260 -1640 {
lab=R5}
N 1205 -1620 1260 -1620 {
lab=R6}
N 1205 -1600 1260 -1600 {
lab=C2}
N 1495 -1640 1540 -1640 {
lab=R5}
N 1495 -1620 1540 -1620 {
lab=R6}
N 1495 -1600 1540 -1600 {
lab=C3}
N 1810 -1640 1860 -1640 {
lab=R5}
N 1810 -1620 1860 -1620 {
lab=R6}
N 1815 -1600 1860 -1600 {
lab=C4}
N 2165 -1640 2200 -1640 {
lab=R5}
N 2165 -1620 2200 -1620 {
lab=R6}
N 2170 -1600 2200 -1600 {
lab=C5}
N 2415 -1640 2470 -1640 {
lab=R5}
N 2420 -1620 2470 -1620 {
lab=R6}
N 2420 -1600 2470 -1600 {
lab=C6}
N 2430 -1850 2480 -1850 {
lab=R5}
N 2435 -1830 2480 -1830 {
lab=R6}
N 2435 -1810 2480 -1810 {
lab=VSS}
N 2435 -1810 2435 -1750 {
lab=VSS}
N 935 -1850 990 -1850 {
lab=R6}
N 935 -1830 990 -1830 {
lab=VSS}
N 935 -1810 990 -1810 {
lab=C1}
N 1200 -1850 1260 -1850 {
lab=R6}
N 1200 -1830 1260 -1830 {
lab=VSS}
N 1200 -1810 1260 -1810 {
lab=C2}
N 1780 -1850 1840 -1850 {
lab=R6}
N 1780 -1830 1840 -1830 {
lab=VSS}
N 1780 -1810 1840 -1810 {
lab=C4}
N 935 -2050 990 -2050 {
lab=R6}
N 935 -2030 990 -2030 {
lab=VSS}
N 935 -2010 990 -2010 {
lab=C0}
N 1200 -2050 1260 -2050 {
lab=R6}
N 1205 -2030 1260 -2030 {
lab=VSS}
N 1205 -2010 1260 -2010 {
lab=C3}
N 1795 -2050 1840 -2050 {
lab=R6}
N 1795 -2030 1840 -2030 {
lab=VSS}
N 1795 -2010 1840 -2010 {
lab=C5}
N 2135 -2050 2180 -2050 {
lab=R6}
N 2135 -2030 2180 -2030 {
lab=VSS}
N 2135 -2010 2180 -2010 {
lab=C6}
N 1720 -1305 1720 -1270 {
lab=OUT+}
N 1720 -1250 1720 -1215 {
lab=OUT-}
N 1720 -1100 1720 -1070 {
lab=OUT+}
N 1720 -1050 1720 -1015 {
lab=OUT-}
N 1450 -1300 1450 -1260 {
lab=OUT+}
N 1450 -1240 1450 -1200 {
lab=OUT-}
N 1450 -1115 1450 -1080 {
lab=OUT+}
N 1450 -1060 1450 -1035 {
lab=OUT-}
N 1180 -1125 1180 -1080 {
lab=OUT+}
N 1180 -1060 1180 -1020 {
lab=OUT-}
N 910 -1115 910 -1070 {
lab=OUT+}
N 910 -1050 910 -1015 {
lab=OUT-}
N 910 -910 910 -870 {
lab=OUT+}
N 910 -850 910 -810 {
lab=OUT-}
N 1450 -910 1450 -870 {
lab=OUT+}
N 1450 -850 1450 -810 {
lab=OUT-}
N 2040 -910 2040 -870 {
lab=OUT+}
N 2040 -850 2040 -810 {
lab=OUT-}
N 2660 -910 2660 -870 {
lab=OUT+}
N 2660 -850 2660 -810 {
lab=OUT-}
N 3200 -680 3200 -640 {
lab=OUT+}
N 3200 -620 3200 -580 {
lab=OUT-}
N 2930 -680 2930 -640 {
lab=OUT+}
N 2930 -620 2930 -580 {
lab=OUT-}
N 2650 -680 2650 -640 {
lab=OUT+}
N 2650 -620 2650 -580 {
lab=OUT-}
N 2360 -680 2360 -640 {
lab=OUT+}
N 2360 -620 2360 -580 {
lab=OUT-}
N 2020 -680 2020 -640 {
lab=OUT+}
N 2020 -620 2020 -580 {
lab=OUT-}
N 1690 -680 1690 -640 {
lab=OUT+}
N 1690 -620 1690 -580 {
lab=OUT-}
N 1430 -680 1430 -640 {
lab=OUT+}
N 1430 -620 1430 -580 {
lab=OUT-}
N 890 -680 890 -640 {
lab=OUT+}
N 890 -620 890 -580 {
lab=OUT-}
N 890 -460 890 -420 {
lab=OUT+}
N 890 -400 890 -360 {
lab=OUT-}
N 1160 -460 1160 -420 {
lab=OUT+}
N 1160 -400 1160 -360 {
lab=OUT-}
N 1430 -460 1430 -420 {
lab=OUT+}
N 1430 -400 1430 -360 {
lab=OUT-}
N 2010 -450 2010 -410 {
lab=OUT+}
N 2010 -390 2010 -350 {
lab=OUT-}
N 2650 -440 2650 -400 {
lab=OUT+}
N 2650 -380 2650 -340 {
lab=OUT-}
N 2930 -440 2930 -400 {
lab=OUT+}
N 2930 -380 2930 -340 {
lab=OUT-}
N 3200 -440 3200 -400 {
lab=OUT+}
N 3200 -380 3200 -340 {
lab=OUT-}
N 1160 -260 1160 -220 {
lab=OUT+}
N 1160 -200 1160 -160 {
lab=OUT-}
N 1430 -260 1430 -220 {
lab=OUT+}
N 1430 -200 1430 -160 {
lab=OUT-}
N 2000 -250 2000 -210 {
lab=OUT+}
N 2000 -190 2000 -150 {
lab=OUT-}
N 2350 -240 2350 -200 {
lab=OUT+}
N 2350 -180 2350 -140 {
lab=OUT-}
N 2930 -240 2930 -200 {
lab=OUT+}
N 2930 -180 2930 -140 {
lab=OUT-}
N 1170 -2070 1170 -2030 {
lab=OUT+}
N 1170 -2010 1170 -1970 {
lab=OUT-}
N 1440 -2070 1440 -2030 {
lab=OUT+}
N 1440 -2010 1440 -1970 {
lab=OUT-}
N 2020 -2070 2020 -2030 {
lab=OUT+}
N 2020 -2010 2020 -1970 {
lab=OUT-}
N 2360 -2070 2360 -2030 {
lab=OUT+}
N 2360 -2010 2360 -1970 {
lab=OUT-}
N 2940 -2070 2940 -2030 {
lab=OUT+}
N 2940 -2010 2940 -1970 {
lab=OUT-}
N 3210 -1870 3210 -1830 {
lab=OUT+}
N 3210 -1810 3210 -1770 {
lab=OUT-}
N 2930 -1870 2930 -1830 {
lab=OUT+}
N 2930 -1810 2930 -1770 {
lab=OUT-}
N 2660 -1870 2660 -1830 {
lab=OUT+}
N 2660 -1810 2660 -1770 {
lab=OUT-}
N 2020 -1870 2020 -1830 {
lab=OUT+}
N 2020 -1810 2020 -1770 {
lab=OUT-}
N 1440 -1870 1440 -1830 {
lab=OUT+}
N 1440 -1810 1440 -1770 {
lab=OUT-}
N 1170 -1870 1170 -1830 {
lab=OUT+}
N 1170 -1810 1170 -1770 {
lab=OUT-}
N 910 -1660 910 -1620 {
lab=OUT+}
N 910 -1600 910 -1560 {
lab=OUT-}
N 1180 -1660 1180 -1620 {
lab=OUT+}
N 1180 -1600 1180 -1560 {
lab=OUT-}
N 1440 -1660 1440 -1620 {
lab=OUT+}
N 1440 -1600 1440 -1560 {
lab=OUT-}
N 1720 -1660 1720 -1620 {
lab=OUT+}
N 1720 -1600 1720 -1560 {
lab=OUT-}
N 2040 -1660 2040 -1620 {
lab=OUT+}
N 2040 -1600 2040 -1560 {
lab=OUT-}
N 2380 -1660 2380 -1620 {
lab=OUT+}
N 2380 -1600 2380 -1560 {
lab=OUT-}
N 2650 -1660 2650 -1620 {
lab=OUT+}
N 2650 -1600 2650 -1560 {
lab=OUT-}
N 2950 -1660 2950 -1620 {
lab=OUT+}
N 2950 -1600 2950 -1560 {
lab=OUT-}
N 3220 -1660 3220 -1620 {
lab=OUT+}
N 3220 -1600 3220 -1560 {
lab=OUT-}
N 910 -1290 910 -1250 {
lab=OUT+}
N 910 -1230 910 -1190 {
lab=OUT-}
N 1180 -1290 1180 -1250 {
lab=OUT+}
N 1180 -1230 1180 -1190 {
lab=OUT-}
N 2640 -1305 2640 -1270 {
lab=OUT+}
N 2640 -1250 2640 -1215 {
lab=OUT-}
N 2940 -1305 2940 -1270 {
lab=OUT+}
N 2940 -1250 2940 -1215 {
lab=OUT-}
N 3210 -1305 3210 -1270 {
lab=OUT+}
N 3210 -1250 3210 -1215 {
lab=OUT-}
N 1440 -1475 1440 -1440 {
lab=OUT+}
N 1440 -1420 1440 -1385 {
lab=OUT-}
N 2040 -1475 2040 -1440 {
lab=OUT+}
N 2040 -1420 2040 -1385 {
lab=OUT-}
N 2650 -1475 2650 -1440 {
lab=OUT+}
N 2650 -1420 2650 -1385 {
lab=OUT-}
N 2130 -200 2170 -200 {
lab=R0}
N 1785 -210 1820 -210 {
lab=R0}
N 1315 -2450 1705 -2450 {
lab=VDD}
N 1315 -2270 1705 -2270 {
lab=VSS}
N 1165 -2380 1205 -2380 {
lab=B9}
N 1165 -2360 1205 -2360 {
lab=B8}
N 1165 -2340 1205 -2340 {
lab=B7}
N 1555 -2380 1595 -2380 {
lab=B12}
N 1555 -2360 1595 -2360 {
lab=B11}
N 1555 -2340 1595 -2340 {
lab=B10}
N 1435 -2420 1475 -2420 {
lab=C6}
N 1435 -2400 1475 -2400 {
lab=C5}
N 1435 -2380 1445 -2380 {
lab=C4}
N 1445 -2380 1475 -2380 {
lab=C4}
N 1435 -2360 1475 -2360 {
lab=C3}
N 1435 -2340 1475 -2340 {
lab=C2}
N 1435 -2300 1475 -2300 {
lab=C0}
N 1825 -2420 1865 -2420 {
lab=R6}
N 1825 -2400 1865 -2400 {
lab=R5}
N 1825 -2380 1835 -2380 {
lab=R4}
N 1835 -2380 1865 -2380 {
lab=R4}
N 1825 -2360 1865 -2360 {
lab=R3}
N 1825 -2340 1865 -2340 {
lab=R2}
N 1825 -2320 1865 -2320 {
lab=R1}
N 1435 -2320 1475 -2320 {
lab=C1}
N 1825 -2300 1865 -2300 {
lab=R0}
N 980 -470 980 -440 {
lab=R0}
N 2380 -1305 2380 -1270 {
lab=OUT+}
N 2380 -1250 2380 -1215 {
lab=OUT-}
N 2390 -1105 2390 -1070 {
lab=OUT+}
N 2390 -1050 2390 -1015 {
lab=OUT-}
N 2650 -1105 2650 -1070 {
lab=OUT+}
N 2650 -1050 2650 -1015 {
lab=OUT-}
N 2950 -1105 2950 -1070 {
lab=OUT+}
N 2950 -1050 2950 -1015 {
lab=OUT-}
N 3220 -1105 3220 -1070 {
lab=OUT+}
N 3220 -1050 3220 -1015 {
lab=OUT-}
N 1160 -260 1430 -260 {
lab=OUT+}
N 1160 -160 1160 -150 {
lab=OUT-}
N 1160 -150 1430 -150 {
lab=OUT-}
N 1430 -160 1430 -150 {
lab=OUT-}
N 1450 -1030 1450 -1010 {
lab=OUT-}
N 1450 -1035 1450 -1030 {
lab=OUT-}
N 2905 -2345 2905 -2305 {
lab=C32_D}
N 2905 -2375 2915 -2375 {
lab=VSS}
N 2915 -2375 2915 -2275 {
lab=VSS}
N 2905 -2275 2915 -2275 {
lab=VSS}
N 2905 -2275 2915 -2275 {
lab=VSS}
N 2915 -2275 2915 -2245 {
lab=VSS}
N 2905 -2245 2915 -2245 {
lab=VSS}
N 2905 -2245 2905 -2215 {
lab=VSS}
N 2840 -2375 2865 -2375 {
lab=C32_U}
N 2840 -2425 2840 -2375 {
lab=C32_U}
N 2840 -2325 2905 -2325 {
lab=C32_D}
N 2840 -2325 2840 -2275 {
lab=C32_D}
N 2840 -2275 2865 -2275 {
lab=C32_D}
N 2840 -2425 2905 -2425 {
lab=C32_U}
N 2905 -2485 2905 -2405 {
lab=C32_U}
N 2455 -2570 2455 -2540 {
lab=GND}
N 2455 -2660 2455 -2630 {
lab=VSS}
N 2515 -2660 2515 -2630 {
lab=VDD}
N 2515 -2570 2515 -2540 {
lab=VSS}
N 2675 -2660 2675 -2630 {
lab=VDD}
N 2675 -2570 2675 -2540 {
lab=C32_U}
N 1835 -2790 1835 -2760 {
lab=B10}
N 1835 -2700 1835 -2670 {
lab=VSS}
N 1875 -2770 1875 -2740 {
lab=B11}
N 1875 -2680 1875 -2650 {
lab=VSS}
N 1915 -2750 1915 -2720 {
lab=B12}
N 1915 -2660 1915 -2630 {
lab=VSS}
N 1795 -2810 1795 -2780 {
lab=B9}
N 1795 -2720 1795 -2690 {
lab=VSS}
N 1755 -2830 1755 -2800 {
lab=B8}
N 1755 -2740 1755 -2710 {
lab=VSS}
N 1715 -2850 1715 -2820 {
lab=B7}
N 1715 -2760 1715 -2730 {
lab=VSS}
N 2905 -2535 2905 -2485 {
lab=C32_U}
N 2675 -2535 2905 -2535 {
lab=C32_U}
N 2675 -2540 2675 -2535 {
lab=C32_U}
N 3110 -2495 3140 -2495 {
lab=OUT-}
N 3140 -2495 3160 -2495 {
lab=OUT-}
N 3160 -2435 3160 -2405 {
lab=VDD}
N 3260 -2515 3290 -2515 {
lab=OUT+}
N 3290 -2515 3310 -2515 {
lab=OUT+}
N 3310 -2455 3310 -2425 {
lab=VDD}
N 3080 -2495 3110 -2495 {
lab=OUT-}
N 3150 -2515 3260 -2515 {
lab=OUT+}
N 3120 -2515 3150 -2515 {
lab=OUT+}
N 3050 -2495 3080 -2495 {
lab=OUT-}
N 3050 -2515 3120 -2515 {
lab=OUT+}
N 3030 -2515 3050 -2515 {
lab=OUT+}
N 2705 -2000 2705 -1995 {
lab=#net37}
C {MSB_UNIT_CELL.sym} 1900 -1420 0 0 {name=x2}
C {MSB_UNIT_CELL.sym} 2240 -1250 0 0 {name=x3}
C {MSB_UNIT_CELL.sym} 2250 -1050 0 0 {name=x4}
C {MSB_UNIT_CELL.sym} 1580 -1250 0 0 {name=x5}
C {MSB_UNIT_CELL.sym} 1580 -1050 0 0 {name=x6}
C {MSB_UNIT_CELL.sym} 1900 -850 0 0 {name=x7}
C {CM_32_s.sym} 2290 -1420 0 0 {name=x8}
C {CM_32_s.sym} 1630 -1420 0 0 {name=x9}
C {CM_32_s.sym} 2300 -850 0 0 {name=x10}
C {CM_32_s.sym} 1630 -850 0 0 {name=x11}
C {MSB_UNIT_CELL.sym} 1580 -1600 0 0 {name=x12}
C {MSB_UNIT_CELL.sym} 1900 -1600 0 0 {name=x13}
C {MSB_UNIT_CELL.sym} 2240 -1600 0 0 {name=x14}
C {MSB_UNIT_CELL.sym} 1300 -1600 0 0 {name=x15}
C {MSB_UNIT_CELL.sym} 2510 -1600 0 0 {name=x16}
C {MSB_UNIT_CELL.sym} 1300 -1420 0 0 {name=x17}
C {MSB_UNIT_CELL.sym} 1310 -1240 0 0 {name=x18}
C {MSB_UNIT_CELL.sym} 1310 -1060 0 0 {name=x19}
C {MSB_UNIT_CELL.sym} 1310 -850 0 0 {name=x20}
C {MSB_UNIT_CELL.sym} 1290 -620 0 0 {name=x21}
C {MSB_UNIT_CELL.sym} 1550 -620 0 0 {name=x22}
C {MSB_UNIT_CELL.sym} 1880 -620 0 0 {name=x23}
C {MSB_UNIT_CELL.sym} 2220 -620 0 0 {name=x24}
C {MSB_UNIT_CELL.sym} 2510 -620 0 0 {name=x25}
C {MSB_UNIT_CELL.sym} 2520 -850 0 0 {name=x26}
C {MSB_UNIT_CELL.sym} 2510 -1050 0 0 {name=x27}
C {MSB_UNIT_CELL.sym} 2500 -1250 0 0 {name=x28}
C {MSB_UNIT_CELL.sym} 2510 -1420 0 0 {name=x29}
C {MSB_UNIT_CELL.sym} 1040 -1600 0 0 {name=x30}
C {CM_32_s.sym} 1090 -1420 0 0 {name=x31}
C {MSB_UNIT_CELL.sym} 1040 -1230 0 0 {name=x32}
C {MSB_UNIT_CELL.sym} 1040 -1060 0 0 {name=x35}
C {CM_32_s.sym} 1090 -630 0 0 {name=x33}
C {CM_32_s.sym} 1090 -850 0 0 {name=x34}
C {MSB_UNIT_CELL.sym} 770 -1600 0 0 {name=x36}
C {CM_32_s.sym} 820 -1420 0 0 {name=x37}
C {MSB_UNIT_CELL.sym} 770 -1230 0 0 {name=x38}
C {MSB_UNIT_CELL.sym} 750 -620 0 0 {name=x39}
C {MSB_UNIT_CELL.sym} 770 -1050 0 0 {name=x40}
C {MSB_UNIT_CELL.sym} 770 -850 0 0 {name=x41}
C {MSB_UNIT_CELL.sym} 3080 -1600 0 0 {name=x42}
C {CM_32_s.sym} 3130 -1420 0 0 {name=x43}
C {MSB_UNIT_CELL.sym} 3070 -1250 0 0 {name=x44}
C {MSB_UNIT_CELL.sym} 3060 -620 0 0 {name=x45}
C {CM_32_s.sym} 3130 -850 0 0 {name=x47}
C {MSB_UNIT_CELL.sym} 2810 -1600 0 0 {name=x48}
C {CM_32_s.sym} 2860 -1420 0 0 {name=x49}
C {MSB_UNIT_CELL.sym} 2800 -1250 0 0 {name=x50}
C {MSB_UNIT_CELL.sym} 2790 -620 0 0 {name=x51}
C {MSB_UNIT_CELL.sym} 2810 -1050 0 0 {name=x52}
C {MSB_UNIT_CELL.sym} 3080 -1050 0 0 {name=x46}
C {CM_32_s.sym} 2860 -850 0 0 {name=x53}
C {MSB_UNIT_CELL.sym} 1290 -400 0 0 {name=x54}
C {MSB_UNIT_CELL.sym} 1020 -400 0 0 {name=x55}
C {MSB_UNIT_CELL.sym} 750 -400 0 0 {name=x56}
C {CM_32_s.sym} 1600 -410 0 0 {name=x57}
C {MSB_UNIT_CELL.sym} 1870 -390 0 0 {name=x58}
C {CM_32_s.sym} 2270 -390 0 0 {name=x59}
C {MSB_UNIT_CELL.sym} 2510 -380 0 0 {name=x60}
C {MSB_UNIT_CELL.sym} 3060 -380 0 0 {name=x61}
C {MSB_UNIT_CELL.sym} 2790 -380 0 0 {name=x62}
C {MSB_UNIT_CELL.sym} 1290 -200 0 0 {name=x63}
C {MSB_UNIT_CELL.sym} 1020 -200 0 0 {name=x64}
C {CM_32_s.sym} 1600 -210 0 0 {name=x65}
C {MSB_UNIT_CELL.sym} 1860 -190 0 0 {name=x66}
C {MSB_UNIT_CELL.sym} 2210 -180 0 0 {name=x67}
C {CM_32_s.sym} 2560 -180 0 0 {name=x68}
C {MSB_UNIT_CELL.sym} 2790 -180 0 0 {name=x69}
C {MSB_UNIT_CELL.sym} 1300 -1810 0 0 {name=x70}
C {MSB_UNIT_CELL.sym} 1030 -1810 0 0 {name=x71}
C {CM_32_s.sym} 1630 -1810 0 0 {name=x73}
C {MSB_UNIT_CELL.sym} 1880 -1810 0 0 {name=x74}
C {CM_32_s.sym} 2280 -1810 0 0 {name=x75}
C {MSB_UNIT_CELL.sym} 2520 -1810 0 0 {name=x76}
C {MSB_UNIT_CELL.sym} 3070 -1810 0 0 {name=x77}
C {MSB_UNIT_CELL.sym} 2790 -1810 0 0 {name=x78}
C {MSB_UNIT_CELL.sym} 1300 -2010 0 0 {name=x72}
C {MSB_UNIT_CELL.sym} 1030 -2010 0 0 {name=x79}
C {CM_32_s.sym} 1620 -2010 0 0 {name=x80}
C {MSB_UNIT_CELL.sym} 1880 -2010 0 0 {name=x81}
C {CM_32_s.sym} 2570 -2010 0 0 {name=x82}
C {MSB_UNIT_CELL.sym} 2220 -2010 0 0 {name=x83}
C {MSB_UNIT_CELL.sym} 2800 -2010 0 0 {name=x85}
C {devices/lab_pin.sym} 2090 -1950 0 0 {name=p1 sig_type=std_logic lab=VSS}
C {devices/lab_pin.sym} 2120 -1750 0 0 {name=p2 sig_type=std_logic lab=VSS}
C {devices/lab_pin.sym} 2130 -1540 0 0 {name=p3 sig_type=std_logic lab=VSS}
C {devices/lab_pin.sym} 2140 -1360 0 0 {name=p4 sig_type=std_logic lab=VSS}
C {devices/lab_pin.sym} 1510 -1170 0 0 {name=p5 sig_type=std_logic lab=VSS}
C {devices/lab_pin.sym} 2430 -1190 0 0 {name=p6 sig_type=std_logic lab=VSS}
C {devices/lab_pin.sym} 2690 -990 0 0 {name=p7 sig_type=std_logic lab=VSS}
C {devices/lab_pin.sym} 2710 -790 0 0 {name=p8 sig_type=std_logic lab=VSS}
C {devices/lab_pin.sym} 2690 -560 0 0 {name=p9 sig_type=std_logic lab=VSS}
C {devices/lab_pin.sym} 2700 -320 0 0 {name=p10 sig_type=std_logic lab=VSS}
C {devices/lab_pin.sym} 2690 -120 0 0 {name=p11 sig_type=std_logic lab=VSS}
C {devices/lab_pin.sym} 2100 -2110 0 0 {name=p12 sig_type=std_logic lab=VDD}
C {devices/lab_pin.sym} 2110 -1690 0 0 {name=p13 sig_type=std_logic lab=VDD}
C {devices/lab_pin.sym} 2070 -1900 0 0 {name=p14 sig_type=std_logic lab=VDD}
C {devices/lab_pin.sym} 2130 -1500 0 0 {name=p15 sig_type=std_logic lab=VDD}
C {devices/lab_pin.sym} 2160 -1330 0 0 {name=p16 sig_type=std_logic lab=VDD}
C {devices/lab_pin.sym} 1460 -1140 0 0 {name=p17 sig_type=std_logic lab=VDD}
C {devices/lab_pin.sym} 2690 -1140 0 0 {name=p18 sig_type=std_logic lab=VDD}
C {devices/lab_pin.sym} 2200 -940 0 0 {name=p19 sig_type=std_logic lab=VDD}
C {devices/lab_pin.sym} 2140 -720 0 0 {name=p20 sig_type=std_logic lab=VDD}
C {devices/lab_pin.sym} 2080 -490 0 0 {name=p21 sig_type=std_logic lab=VDD}
C {devices/lab_pin.sym} 2080 -290 0 0 {name=p22 sig_type=std_logic lab=VDD}
C {devices/lab_pin.sym} 2120 -960 0 0 {name=p23 sig_type=std_logic lab=C32_U}
C {devices/lab_pin.sym} 2190 -840 0 0 {name=p24 sig_type=std_logic lab=C32_D}
C {devices/lab_pin.sym} 2175 -1430 0 0 {name=p25 sig_type=std_logic lab=C32_U}
C {devices/lab_pin.sym} 2175 -1410 0 0 {name=p26 sig_type=std_logic lab=C32_D}
C {devices/lab_pin.sym} 1520 -1430 0 0 {name=p27 sig_type=std_logic lab=C32_U}
C {devices/lab_pin.sym} 1520 -1410 0 0 {name=p28 sig_type=std_logic lab=C32_D}
C {devices/lab_pin.sym} 940 -220 0 0 {name=p29 sig_type=std_logic lab=R0}
C {devices/lab_pin.sym} 1240 -220 0 0 {name=p30 sig_type=std_logic lab=R0}
C {devices/lab_pin.sym} 1790 -210 0 0 {name=p31 sig_type=std_logic lab=R0}
C {devices/lab_pin.sym} 2130 -200 0 0 {name=p32 sig_type=std_logic lab=R0}
C {devices/lab_pin.sym} 2730 -200 0 0 {name=p33 sig_type=std_logic lab=R0}
C {devices/lab_pin.sym} 2720 -400 0 0 {name=p34 sig_type=std_logic lab=R0}
C {devices/lab_pin.sym} 2990 -400 0 0 {name=p35 sig_type=std_logic lab=R0}
C {devices/lab_pin.sym} 2430 -400 0 0 {name=p36 sig_type=std_logic lab=R0}
C {devices/lab_pin.sym} 650 -440 0 0 {name=p37 sig_type=std_logic lab=R0}
C {devices/lab_pin.sym} 1210 -440 0 0 {name=p39 sig_type=std_logic lab=R0}
C {devices/lab_pin.sym} 1810 -430 0 0 {name=p40 sig_type=std_logic lab=R0}
C {devices/lab_pin.sym} 2420 -660 0 0 {name=p42 sig_type=std_logic lab=R0}
C {devices/lab_pin.sym} 2700 -660 0 0 {name=p43 sig_type=std_logic lab=R0}
C {devices/lab_pin.sym} 2980 -660 0 0 {name=p44 sig_type=std_logic lab=R0}
C {devices/lab_pin.sym} 650 -420 0 0 {name=p45 sig_type=std_logic lab=R1}
C {devices/lab_pin.sym} 920 -420 0 0 {name=p46 sig_type=std_logic lab=R1}
C {devices/lab_pin.sym} 1200 -420 0 0 {name=p47 sig_type=std_logic lab=R1}
C {devices/lab_pin.sym} 1810 -410 0 0 {name=p48 sig_type=std_logic lab=R1}
C {devices/lab_pin.sym} 2140 -640 0 0 {name=p49 sig_type=std_logic lab=R1}
C {devices/lab_pin.sym} 2430 -640 0 0 {name=p50 sig_type=std_logic lab=R1}
C {devices/lab_pin.sym} 2700 -640 0 0 {name=p51 sig_type=std_logic lab=R1}
C {devices/lab_pin.sym} 2980 -640 0 0 {name=p52 sig_type=std_logic lab=R1}
C {devices/lab_pin.sym} 930 -200 0 0 {name=p53 sig_type=std_logic lab=C0}
C {devices/lab_pin.sym} 1230 -200 0 0 {name=p54 sig_type=std_logic lab=C1}
C {devices/lab_pin.sym} 1780 -190 0 0 {name=p55 sig_type=std_logic lab=C2}
C {devices/lab_pin.sym} 2130 -180 0 0 {name=p56 sig_type=std_logic lab=C3}
C {devices/lab_pin.sym} 2720 -180 0 0 {name=p57 sig_type=std_logic lab=C6}
C {devices/lab_pin.sym} 2420 -380 0 0 {name=p58 sig_type=std_logic lab=C4}
C {devices/lab_pin.sym} 2700 -380 0 0 {name=p59 sig_type=std_logic lab=C5}
C {devices/lab_pin.sym} 2980 -380 0 0 {name=p60 sig_type=std_logic lab=VSS}
C {devices/lab_pin.sym} 650 -400 0 0 {name=p61 sig_type=std_logic lab=C0}
C {devices/lab_pin.sym} 930 -400 0 0 {name=p62 sig_type=std_logic lab=C1}
C {devices/lab_pin.sym} 1200 -400 0 0 {name=p63 sig_type=std_logic lab=C2}
C {devices/lab_pin.sym} 1800 -390 0 0 {name=p64 sig_type=std_logic lab=C3}
C {devices/lab_pin.sym} 2140 -620 0 0 {name=p65 sig_type=std_logic lab=C4}
C {devices/lab_pin.sym} 2420 -620 0 0 {name=p66 sig_type=std_logic lab=C5}
C {devices/lab_pin.sym} 2700 -620 0 0 {name=p67 sig_type=std_logic lab=C6}
C {devices/lab_pin.sym} 2980 -620 0 0 {name=p68 sig_type=std_logic lab=VSS}
C {devices/lab_pin.sym} 645 -660 0 0 {name=p69 sig_type=std_logic lab=R1}
C {devices/lab_pin.sym} 665 -890 0 0 {name=p70 sig_type=std_logic lab=R1}
C {devices/lab_pin.sym} 1220 -660 0 0 {name=p71 sig_type=std_logic lab=R1}
C {devices/lab_pin.sym} 1210 -890 0 0 {name=p72 sig_type=std_logic lab=R1}
C {devices/lab_pin.sym} 1470 -660 0 0 {name=p73 sig_type=std_logic lab=R1}
C {devices/lab_pin.sym} 1790 -660 0 0 {name=p74 sig_type=std_logic lab=R1}
C {devices/lab_pin.sym} 1805 -890 0 0 {name=p75 sig_type=std_logic lab=R1}
C {devices/lab_pin.sym} 2425 -890 0 0 {name=p76 sig_type=std_logic lab=R1}
C {devices/lab_pin.sym} 645 -640 0 0 {name=p77 sig_type=std_logic lab=R2}
C {devices/lab_pin.sym} 660 -870 0 0 {name=p78 sig_type=std_logic lab=R2}
C {devices/lab_pin.sym} 1225 -640 0 0 {name=p79 sig_type=std_logic lab=R2}
C {devices/lab_pin.sym} 1210 -870 0 0 {name=p80 sig_type=std_logic lab=R2}
C {devices/lab_pin.sym} 1470 -640 0 0 {name=p81 sig_type=std_logic lab=R2}
C {devices/lab_pin.sym} 1795 -640 0 0 {name=p82 sig_type=std_logic lab=R2}
C {devices/lab_pin.sym} 1805 -870 0 0 {name=p83 sig_type=std_logic lab=R2}
C {devices/lab_pin.sym} 2430 -870 0 0 {name=p84 sig_type=std_logic lab=R2}
C {devices/lab_pin.sym} 640 -620 0 0 {name=p85 sig_type=std_logic lab=C0}
C {devices/lab_pin.sym} 660 -850 0 0 {name=p86 sig_type=std_logic lab=C1}
C {devices/lab_pin.sym} 1220 -620 0 0 {name=p87 sig_type=std_logic lab=C2}
C {devices/lab_pin.sym} 1220 -850 0 0 {name=p88 sig_type=std_logic lab=C3}
C {devices/lab_pin.sym} 1470 -620 0 0 {name=p89 sig_type=std_logic lab=C4}
C {devices/lab_pin.sym} 1795 -620 0 0 {name=p90 sig_type=std_logic lab=C5}
C {devices/lab_pin.sym} 1810 -850 0 0 {name=p91 sig_type=std_logic lab=C6}
C {devices/lab_pin.sym} 2450 -850 0 0 {name=p92 sig_type=std_logic lab=VSS}
C {devices/lab_pin.sym} 650 -1090 0 0 {name=p93 sig_type=std_logic lab=R2}
C {devices/lab_pin.sym} 940 -1100 0 0 {name=p94 sig_type=std_logic lab=R2}
C {devices/lab_pin.sym} 1215 -1100 0 0 {name=p95 sig_type=std_logic lab=R2}
C {devices/lab_pin.sym} 1490 -1090 0 0 {name=p96 sig_type=std_logic lab=R2}
C {devices/lab_pin.sym} 2160 -1090 0 0 {name=p97 sig_type=std_logic lab=R2}
C {devices/lab_pin.sym} 2420 -1090 0 0 {name=p98 sig_type=std_logic lab=R2}
C {devices/lab_pin.sym} 2705 -1090 0 0 {name=p99 sig_type=std_logic lab=R2}
C {devices/lab_pin.sym} 2975 -1090 0 0 {name=p100 sig_type=std_logic lab=R2}
C {devices/lab_pin.sym} 650 -1070 0 0 {name=p101 sig_type=std_logic lab=R3}
C {devices/lab_pin.sym} 940 -1080 0 0 {name=p102 sig_type=std_logic lab=R3}
C {devices/lab_pin.sym} 1220 -1080 0 0 {name=p103 sig_type=std_logic lab=R3}
C {devices/lab_pin.sym} 1495 -1070 0 0 {name=p104 sig_type=std_logic lab=R3}
C {devices/lab_pin.sym} 2160 -1070 0 0 {name=p105 sig_type=std_logic lab=R3}
C {devices/lab_pin.sym} 2420 -1070 0 0 {name=p106 sig_type=std_logic lab=R3}
C {devices/lab_pin.sym} 2705 -1070 0 0 {name=p107 sig_type=std_logic lab=R3}
C {devices/lab_pin.sym} 2985 -1070 0 0 {name=p108 sig_type=std_logic lab=R3}
C {devices/lab_pin.sym} 655 -1050 0 0 {name=p109 sig_type=std_logic lab=C0}
C {devices/lab_pin.sym} 950 -1060 0 0 {name=p110 sig_type=std_logic lab=C1}
C {devices/lab_pin.sym} 1215 -1060 0 0 {name=p111 sig_type=std_logic lab=C2}
C {devices/lab_pin.sym} 1490 -1050 0 0 {name=p112 sig_type=std_logic lab=C3}
C {devices/lab_pin.sym} 2165 -1050 0 0 {name=p113 sig_type=std_logic lab=C4}
C {devices/lab_pin.sym} 2430 -1050 0 0 {name=p114 sig_type=std_logic lab=C5}
C {devices/lab_pin.sym} 2705 -1050 0 0 {name=p115 sig_type=std_logic lab=C6}
C {devices/lab_pin.sym} 2985 -1050 0 0 {name=p116 sig_type=std_logic lab=VSS}
C {devices/lab_pin.sym} 655 -1270 0 0 {name=p117 sig_type=std_logic lab=R3}
C {devices/lab_pin.sym} 950 -1270 0 0 {name=p118 sig_type=std_logic lab=R3}
C {devices/lab_pin.sym} 1200 -1280 0 0 {name=p119 sig_type=std_logic lab=R3}
C {devices/lab_pin.sym} 1480 -1290 0 0 {name=p120 sig_type=std_logic lab=R3}
C {devices/lab_pin.sym} 2145 -1290 0 0 {name=p121 sig_type=std_logic lab=R3}
C {devices/lab_pin.sym} 2405 -1290 0 0 {name=p122 sig_type=std_logic lab=R3}
C {devices/lab_pin.sym} 2715 -1290 0 0 {name=p123 sig_type=std_logic lab=R3}
C {devices/lab_pin.sym} 2975 -1290 0 0 {name=p124 sig_type=std_logic lab=R3}
C {devices/lab_pin.sym} 655 -1250 0 0 {name=p125 sig_type=std_logic lab=R4}
C {devices/lab_pin.sym} 950 -1250 0 0 {name=p126 sig_type=std_logic lab=R4}
C {devices/lab_pin.sym} 1205 -1260 0 0 {name=p127 sig_type=std_logic lab=R4}
C {devices/lab_pin.sym} 1485 -1270 0 0 {name=p128 sig_type=std_logic lab=R4}
C {devices/lab_pin.sym} 2145 -1270 0 0 {name=p129 sig_type=std_logic lab=R4}
C {devices/lab_pin.sym} 2415 -1270 0 0 {name=p130 sig_type=std_logic lab=R4}
C {devices/lab_pin.sym} 2715 -1270 0 0 {name=p131 sig_type=std_logic lab=R4}
C {devices/lab_pin.sym} 2985 -1270 0 0 {name=p132 sig_type=std_logic lab=R4}
C {devices/lab_pin.sym} 660 -1230 0 0 {name=p133 sig_type=std_logic lab=C0}
C {devices/lab_pin.sym} 950 -1230 0 0 {name=p134 sig_type=std_logic lab=C1}
C {devices/lab_pin.sym} 1205 -1240 0 0 {name=p135 sig_type=std_logic lab=C2}
C {devices/lab_pin.sym} 1490 -1250 0 0 {name=p136 sig_type=std_logic lab=C3}
C {devices/lab_pin.sym} 2145 -1250 0 0 {name=p137 sig_type=std_logic lab=C4}
C {devices/lab_pin.sym} 2415 -1250 0 0 {name=p138 sig_type=std_logic lab=C5}
C {devices/lab_pin.sym} 2715 -1250 0 0 {name=p139 sig_type=std_logic lab=C6}
C {devices/lab_pin.sym} 2990 -1250 0 0 {name=p140 sig_type=std_logic lab=VSS}
C {devices/lab_pin.sym} 1215 -1460 0 0 {name=p141 sig_type=std_logic lab=R4}
C {devices/lab_pin.sym} 1815 -1460 0 0 {name=p142 sig_type=std_logic lab=R4}
C {devices/lab_pin.sym} 2420 -1460 0 0 {name=p143 sig_type=std_logic lab=R4}
C {devices/lab_pin.sym} 2715 -1640 0 0 {name=p144 sig_type=std_logic lab=R4}
C {devices/lab_pin.sym} 2980 -1640 0 0 {name=p145 sig_type=std_logic lab=R4}
C {devices/lab_pin.sym} 2700 -1850 0 0 {name=p146 sig_type=std_logic lab=R4}
C {devices/lab_pin.sym} 2975 -1850 0 0 {name=p147 sig_type=std_logic lab=R4}
C {devices/lab_pin.sym} 2735 -2050 0 0 {name=p148 sig_type=std_logic lab=R4}
C {devices/lab_pin.sym} 1215 -1440 0 0 {name=p149 sig_type=std_logic lab=R5}
C {devices/lab_pin.sym} 1810 -1440 0 0 {name=p150 sig_type=std_logic lab=R5}
C {devices/lab_pin.sym} 2420 -1440 0 0 {name=p151 sig_type=std_logic lab=R5}
C {devices/lab_pin.sym} 2710 -1620 0 0 {name=p152 sig_type=std_logic lab=R5}
C {devices/lab_pin.sym} 2985 -1620 0 0 {name=p153 sig_type=std_logic lab=R5}
C {devices/lab_pin.sym} 2700 -1830 0 0 {name=p154 sig_type=std_logic lab=R5}
C {devices/lab_pin.sym} 2985 -1830 0 0 {name=p155 sig_type=std_logic lab=R5}
C {devices/lab_pin.sym} 2740 -2030 0 0 {name=p156 sig_type=std_logic lab=R5}
C {devices/lab_pin.sym} 1240 -1420 0 0 {name=p157 sig_type=std_logic lab=C0}
C {devices/lab_pin.sym} 1825 -1420 0 0 {name=p158 sig_type=std_logic lab=C1}
C {devices/lab_pin.sym} 2420 -1420 0 0 {name=p159 sig_type=std_logic lab=C2}
C {devices/lab_pin.sym} 2705 -1600 0 0 {name=p160 sig_type=std_logic lab=C3}
C {devices/lab_pin.sym} 2990 -1600 0 0 {name=p161 sig_type=std_logic lab=C4}
C {devices/lab_pin.sym} 2700 -1810 0 0 {name=p162 sig_type=std_logic lab=C6}
C {devices/lab_pin.sym} 2980 -1810 0 0 {name=p163 sig_type=std_logic lab=C5}
C {devices/lab_pin.sym} 2735 -2010 0 0 {name=p164 sig_type=std_logic lab=VSS}
C {devices/lab_pin.sym} 670 -1640 0 0 {name=p165 sig_type=std_logic lab=R5}
C {devices/lab_pin.sym} 960 -1640 0 0 {name=p166 sig_type=std_logic lab=R5}
C {devices/lab_pin.sym} 1210 -1640 0 0 {name=p167 sig_type=std_logic lab=R5}
C {devices/lab_pin.sym} 1495 -1640 0 0 {name=p168 sig_type=std_logic lab=R5}
C {devices/lab_pin.sym} 1815 -1640 0 0 {name=p169 sig_type=std_logic lab=R5}
C {devices/lab_pin.sym} 2165 -1640 0 0 {name=p170 sig_type=std_logic lab=R5}
C {devices/lab_pin.sym} 2420 -1640 0 0 {name=p171 sig_type=std_logic lab=R5}
C {devices/lab_pin.sym} 2435 -1850 0 0 {name=p172 sig_type=std_logic lab=R5}
C {devices/lab_pin.sym} 670 -1620 0 0 {name=p173 sig_type=std_logic lab=R6}
C {devices/lab_pin.sym} 955 -1620 0 0 {name=p174 sig_type=std_logic lab=R6}
C {devices/lab_pin.sym} 1210 -1620 0 0 {name=p175 sig_type=std_logic lab=R6}
C {devices/lab_pin.sym} 1500 -1620 0 0 {name=p176 sig_type=std_logic lab=R6}
C {devices/lab_pin.sym} 1815 -1620 0 0 {name=p177 sig_type=std_logic lab=R6}
C {devices/lab_pin.sym} 2170 -1620 0 0 {name=p178 sig_type=std_logic lab=R6}
C {devices/lab_pin.sym} 2425 -1620 0 0 {name=p179 sig_type=std_logic lab=R6}
C {devices/lab_pin.sym} 2440 -1830 0 0 {name=p180 sig_type=std_logic lab=R6}
C {devices/lab_pin.sym} 670 -1600 0 0 {name=p181 sig_type=std_logic lab=C0}
C {devices/lab_pin.sym} 960 -1600 0 0 {name=p182 sig_type=std_logic lab=C1}
C {devices/lab_pin.sym} 1210 -1600 0 0 {name=p183 sig_type=std_logic lab=C2}
C {devices/lab_pin.sym} 1500 -1600 0 0 {name=p184 sig_type=std_logic lab=C3}
C {devices/lab_pin.sym} 1820 -1600 0 0 {name=p185 sig_type=std_logic lab=C4}
C {devices/lab_pin.sym} 2170 -1600 0 0 {name=p186 sig_type=std_logic lab=C5}
C {devices/lab_pin.sym} 2420 -1600 0 0 {name=p187 sig_type=std_logic lab=C6}
C {devices/lab_pin.sym} 935 -1850 0 0 {name=p188 sig_type=std_logic lab=R6}
C {devices/lab_pin.sym} 1200 -1850 0 0 {name=p189 sig_type=std_logic lab=R6}
C {devices/lab_pin.sym} 1790 -1850 0 0 {name=p190 sig_type=std_logic lab=R6}
C {devices/lab_pin.sym} 940 -2050 0 0 {name=p191 sig_type=std_logic lab=R6}
C {devices/lab_pin.sym} 1205 -2050 0 0 {name=p192 sig_type=std_logic lab=R6}
C {devices/lab_pin.sym} 1800 -2050 0 0 {name=p193 sig_type=std_logic lab=R6}
C {devices/lab_pin.sym} 2140 -2050 0 0 {name=p194 sig_type=std_logic lab=R6}
C {devices/lab_pin.sym} 935 -2030 0 0 {name=p195 sig_type=std_logic lab=VSS}
C {devices/lab_pin.sym} 1210 -2030 0 0 {name=p196 sig_type=std_logic lab=VSS}
C {devices/lab_pin.sym} 1800 -2030 0 0 {name=p197 sig_type=std_logic lab=VSS}
C {devices/lab_pin.sym} 2140 -2030 0 0 {name=p198 sig_type=std_logic lab=VSS}
C {devices/lab_pin.sym} 940 -1830 0 0 {name=p199 sig_type=std_logic lab=VSS}
C {devices/lab_pin.sym} 1220 -1830 0 0 {name=p200 sig_type=std_logic lab=VSS}
C {devices/lab_pin.sym} 1800 -1830 0 0 {name=p201 sig_type=std_logic lab=VSS}
C {devices/lab_pin.sym} 935 -2010 0 0 {name=p202 sig_type=std_logic lab=C0}
C {devices/lab_pin.sym} 935 -1810 0 0 {name=p203 sig_type=std_logic lab=C1}
C {devices/lab_pin.sym} 1210 -1810 0 0 {name=p205 sig_type=std_logic lab=C2}
C {devices/lab_pin.sym} 1215 -2010 0 0 {name=p206 sig_type=std_logic lab=C3}
C {devices/lab_pin.sym} 1790 -1810 0 0 {name=p204 sig_type=std_logic lab=C4}
C {devices/lab_pin.sym} 1800 -2010 0 0 {name=p207 sig_type=std_logic lab=C5}
C {devices/lab_pin.sym} 2135 -2010 0 0 {name=p208 sig_type=std_logic lab=C6}
C {devices/iopin.sym} 2265 -2435 0 0 {name=p253 lab=VDD}
C {devices/iopin.sym} 2355 -2435 0 0 {name=p254 lab=VSS}
C {devices/ipin.sym} 1715 -2845 0 0 {name=p255 lab=B7}
C {devices/ipin.sym} 1875 -2770 1 0 {name=p256 lab=B11}
C {devices/ipin.sym} 1755 -2830 1 0 {name=p257 lab=B8}
C {devices/ipin.sym} 1915 -2750 1 0 {name=p258 lab=B12}
C {devices/ipin.sym} 1795 -2810 1 0 {name=p259 lab=B9}
C {devices/ipin.sym} 1835 -2790 1 0 {name=p261 lab=B10}
C {Thermo_Decoder.sym} 1685 -2340 0 0 {name=x84}
C {devices/lab_pin.sym} 1485 -2450 0 0 {name=p209 sig_type=std_logic lab=VDD}
C {devices/lab_pin.sym} 1505 -2270 0 0 {name=p210 sig_type=std_logic lab=VSS}
C {devices/lab_pin.sym} 1475 -2420 0 0 {name=p211 sig_type=std_logic lab=C6}
C {devices/lab_pin.sym} 1475 -2400 0 0 {name=p212 sig_type=std_logic lab=C5}
C {devices/lab_pin.sym} 1475 -2380 0 0 {name=p213 sig_type=std_logic lab=C4}
C {devices/lab_pin.sym} 1475 -2360 0 0 {name=p214 sig_type=std_logic lab=C3}
C {devices/lab_pin.sym} 1475 -2340 0 0 {name=p215 sig_type=std_logic lab=C2}
C {devices/lab_pin.sym} 1475 -2320 0 0 {name=p216 sig_type=std_logic lab=C1}
C {devices/lab_pin.sym} 1475 -2300 0 0 {name=p217 sig_type=std_logic lab=C0}
C {devices/lab_pin.sym} 1865 -2420 0 0 {name=p218 sig_type=std_logic lab=R6}
C {devices/lab_pin.sym} 1865 -2400 0 0 {name=p219 sig_type=std_logic lab=R5}
C {devices/lab_pin.sym} 1865 -2380 0 0 {name=p220 sig_type=std_logic lab=R4}
C {devices/lab_pin.sym} 1865 -2360 0 0 {name=p221 sig_type=std_logic lab=R3}
C {devices/lab_pin.sym} 1865 -2340 0 0 {name=p222 sig_type=std_logic lab=R2}
C {devices/lab_pin.sym} 1865 -2320 0 0 {name=p223 sig_type=std_logic lab=R1}
C {devices/lab_pin.sym} 1165 -2380 0 0 {name=p225 sig_type=std_logic lab=B9}
C {devices/lab_pin.sym} 1165 -2360 0 0 {name=p226 sig_type=std_logic lab=B8}
C {devices/lab_pin.sym} 1165 -2340 0 0 {name=p227 sig_type=std_logic lab=B7}
C {devices/lab_pin.sym} 1555 -2380 0 0 {name=p228 sig_type=std_logic lab=B12}
C {devices/lab_pin.sym} 1555 -2360 0 0 {name=p229 sig_type=std_logic lab=B11}
C {devices/lab_pin.sym} 1555 -2340 0 0 {name=p230 sig_type=std_logic lab=B10}
C {Thermo_Decoder.sym} 1295 -2340 0 0 {name=x86}
C {devices/lab_pin.sym} 1860 -2300 2 0 {name=p224 sig_type=std_logic lab=R0}
C {devices/lab_pin.sym} 980 -460 0 0 {name=p38 sig_type=std_logic lab=R0}
C {devices/lab_pin.sym} 2170 -660 1 0 {name=p41 sig_type=std_logic lab=R0}
C {devices/lab_pin.sym} 1410 -260 0 0 {name=p235 sig_type=std_logic lab=OUT+}
C {devices/lab_pin.sym} 1430 -160 0 0 {name=p236 sig_type=std_logic lab=OUT-}
C {devices/lab_pin.sym} 2000 -240 0 0 {name=p237 sig_type=std_logic lab=OUT+}
C {devices/lab_pin.sym} 2000 -160 0 0 {name=p238 sig_type=std_logic lab=OUT-}
C {devices/lab_pin.sym} 2350 -230 0 0 {name=p239 sig_type=std_logic lab=OUT+}
C {devices/lab_pin.sym} 2350 -150 0 0 {name=p240 sig_type=std_logic lab=OUT-}
C {devices/lab_pin.sym} 2930 -230 0 0 {name=p241 sig_type=std_logic lab=OUT+}
C {devices/lab_pin.sym} 2930 -150 0 0 {name=p242 sig_type=std_logic lab=OUT-}
C {devices/lab_pin.sym} 890 -450 0 0 {name=p243 sig_type=std_logic lab=OUT+}
C {devices/lab_pin.sym} 890 -370 0 0 {name=p244 sig_type=std_logic lab=OUT-}
C {devices/lab_pin.sym} 1160 -450 0 0 {name=p245 sig_type=std_logic lab=OUT+}
C {devices/lab_pin.sym} 1160 -370 0 0 {name=p246 sig_type=std_logic lab=OUT-}
C {devices/lab_pin.sym} 1430 -450 0 0 {name=p247 sig_type=std_logic lab=OUT+}
C {devices/lab_pin.sym} 1430 -370 0 0 {name=p248 sig_type=std_logic lab=OUT-}
C {devices/lab_pin.sym} 2010 -440 0 0 {name=p249 sig_type=std_logic lab=OUT+}
C {devices/lab_pin.sym} 2010 -360 0 0 {name=p250 sig_type=std_logic lab=OUT-}
C {devices/lab_pin.sym} 2650 -430 0 0 {name=p251 sig_type=std_logic lab=OUT+}
C {devices/lab_pin.sym} 2650 -350 0 0 {name=p252 sig_type=std_logic lab=OUT-}
C {devices/lab_pin.sym} 2930 -430 0 0 {name=p260 sig_type=std_logic lab=OUT+}
C {devices/lab_pin.sym} 2930 -350 0 0 {name=p262 sig_type=std_logic lab=OUT-}
C {devices/lab_pin.sym} 3200 -430 0 0 {name=p263 sig_type=std_logic lab=OUT+}
C {devices/lab_pin.sym} 3200 -350 0 0 {name=p280 sig_type=std_logic lab=OUT-}
C {devices/lab_pin.sym} 890 -670 0 0 {name=p281 sig_type=std_logic lab=OUT+}
C {devices/lab_pin.sym} 890 -590 0 0 {name=p282 sig_type=std_logic lab=OUT-}
C {devices/lab_pin.sym} 1430 -670 0 0 {name=p283 sig_type=std_logic lab=OUT+}
C {devices/lab_pin.sym} 1430 -590 0 0 {name=p284 sig_type=std_logic lab=OUT-}
C {devices/lab_pin.sym} 1690 -670 0 0 {name=p285 sig_type=std_logic lab=OUT+}
C {devices/lab_pin.sym} 1690 -590 0 0 {name=p286 sig_type=std_logic lab=OUT-}
C {devices/lab_pin.sym} 2020 -670 0 0 {name=p287 sig_type=std_logic lab=OUT+}
C {devices/lab_pin.sym} 2020 -590 0 0 {name=p288 sig_type=std_logic lab=OUT-}
C {devices/lab_pin.sym} 2360 -670 0 0 {name=p289 sig_type=std_logic lab=OUT+}
C {devices/lab_pin.sym} 2360 -590 0 0 {name=p290 sig_type=std_logic lab=OUT-}
C {devices/lab_pin.sym} 2650 -670 0 0 {name=p291 sig_type=std_logic lab=OUT+}
C {devices/lab_pin.sym} 2650 -590 0 0 {name=p292 sig_type=std_logic lab=OUT-}
C {devices/lab_pin.sym} 2930 -670 0 0 {name=p293 sig_type=std_logic lab=OUT+}
C {devices/lab_pin.sym} 2930 -590 0 0 {name=p294 sig_type=std_logic lab=OUT-}
C {devices/lab_pin.sym} 3200 -670 0 0 {name=p295 sig_type=std_logic lab=OUT+}
C {devices/lab_pin.sym} 3200 -590 0 0 {name=p296 sig_type=std_logic lab=OUT-}
C {devices/lab_pin.sym} 910 -900 0 0 {name=p297 sig_type=std_logic lab=OUT+}
C {devices/lab_pin.sym} 910 -820 0 0 {name=p298 sig_type=std_logic lab=OUT-}
C {devices/lab_pin.sym} 1450 -900 0 0 {name=p299 sig_type=std_logic lab=OUT+}
C {devices/lab_pin.sym} 1450 -820 0 0 {name=p300 sig_type=std_logic lab=OUT-}
C {devices/lab_pin.sym} 2040 -900 0 0 {name=p301 sig_type=std_logic lab=OUT+}
C {devices/lab_pin.sym} 2040 -820 0 0 {name=p302 sig_type=std_logic lab=OUT-}
C {devices/lab_pin.sym} 2660 -900 0 0 {name=p303 sig_type=std_logic lab=OUT+}
C {devices/lab_pin.sym} 2660 -820 0 0 {name=p304 sig_type=std_logic lab=OUT-}
C {devices/lab_pin.sym} 3220 -1100 0 0 {name=p305 sig_type=std_logic lab=OUT+}
C {devices/lab_pin.sym} 3220 -1020 0 0 {name=p306 sig_type=std_logic lab=OUT-}
C {devices/lab_pin.sym} 2950 -1100 0 0 {name=p307 sig_type=std_logic lab=OUT+}
C {devices/lab_pin.sym} 2950 -1020 0 0 {name=p308 sig_type=std_logic lab=OUT-}
C {devices/lab_pin.sym} 2650 -1100 0 0 {name=p309 sig_type=std_logic lab=OUT+}
C {devices/lab_pin.sym} 2650 -1020 0 0 {name=p310 sig_type=std_logic lab=OUT-}
C {devices/lab_pin.sym} 2390 -1100 0 0 {name=p311 sig_type=std_logic lab=OUT+}
C {devices/lab_pin.sym} 2390 -1020 0 0 {name=p312 sig_type=std_logic lab=OUT-}
C {devices/lab_pin.sym} 1720 -1100 0 0 {name=p313 sig_type=std_logic lab=OUT+}
C {devices/lab_pin.sym} 1720 -1020 0 0 {name=p314 sig_type=std_logic lab=OUT-}
C {devices/lab_pin.sym} 1450 -1110 0 0 {name=p315 sig_type=std_logic lab=OUT+}
C {devices/lab_pin.sym} 1450 -1030 0 0 {name=p316 sig_type=std_logic lab=OUT-}
C {devices/lab_pin.sym} 1180 -1110 0 0 {name=p317 sig_type=std_logic lab=OUT+}
C {devices/lab_pin.sym} 1180 -1030 0 0 {name=p318 sig_type=std_logic lab=OUT-}
C {devices/lab_pin.sym} 910 -1100 0 0 {name=p319 sig_type=std_logic lab=OUT+}
C {devices/lab_pin.sym} 910 -1020 0 0 {name=p320 sig_type=std_logic lab=OUT-}
C {devices/lab_pin.sym} 910 -1280 0 0 {name=p321 sig_type=std_logic lab=OUT+}
C {devices/lab_pin.sym} 910 -1200 0 0 {name=p322 sig_type=std_logic lab=OUT-}
C {devices/lab_pin.sym} 1180 -1280 0 0 {name=p323 sig_type=std_logic lab=OUT+}
C {devices/lab_pin.sym} 1180 -1200 0 0 {name=p324 sig_type=std_logic lab=OUT-}
C {devices/lab_pin.sym} 1450 -1290 0 0 {name=p325 sig_type=std_logic lab=OUT+}
C {devices/lab_pin.sym} 1450 -1210 0 0 {name=p326 sig_type=std_logic lab=OUT-}
C {devices/lab_pin.sym} 1720 -1300 0 0 {name=p327 sig_type=std_logic lab=OUT+}
C {devices/lab_pin.sym} 1720 -1220 0 0 {name=p328 sig_type=std_logic lab=OUT-}
C {devices/lab_pin.sym} 2380 -1305 0 0 {name=p329 sig_type=std_logic lab=OUT+}
C {devices/lab_pin.sym} 2380 -1225 0 0 {name=p330 sig_type=std_logic lab=OUT-}
C {devices/lab_pin.sym} 2640 -1300 0 0 {name=p331 sig_type=std_logic lab=OUT+}
C {devices/lab_pin.sym} 2640 -1220 0 0 {name=p332 sig_type=std_logic lab=OUT-}
C {devices/lab_pin.sym} 2940 -1300 0 0 {name=p333 sig_type=std_logic lab=OUT+}
C {devices/lab_pin.sym} 2940 -1220 0 0 {name=p334 sig_type=std_logic lab=OUT-}
C {devices/lab_pin.sym} 3210 -1300 0 0 {name=p335 sig_type=std_logic lab=OUT+}
C {devices/lab_pin.sym} 3210 -1220 0 0 {name=p336 sig_type=std_logic lab=OUT-}
C {devices/lab_pin.sym} 1440 -1475 0 0 {name=p337 sig_type=std_logic lab=OUT+}
C {devices/lab_pin.sym} 1440 -1395 0 0 {name=p338 sig_type=std_logic lab=OUT-}
C {devices/lab_pin.sym} 2040 -1470 0 0 {name=p339 sig_type=std_logic lab=OUT+}
C {devices/lab_pin.sym} 2040 -1390 0 0 {name=p340 sig_type=std_logic lab=OUT-}
C {devices/lab_pin.sym} 2650 -1465 0 0 {name=p341 sig_type=std_logic lab=OUT+}
C {devices/lab_pin.sym} 2650 -1385 0 0 {name=p342 sig_type=std_logic lab=OUT-}
C {devices/lab_pin.sym} 910 -1650 0 0 {name=p343 sig_type=std_logic lab=OUT+}
C {devices/lab_pin.sym} 910 -1570 0 0 {name=p344 sig_type=std_logic lab=OUT-}
C {devices/lab_pin.sym} 1180 -1645 0 0 {name=p345 sig_type=std_logic lab=OUT+}
C {devices/lab_pin.sym} 1180 -1565 0 0 {name=p346 sig_type=std_logic lab=OUT-}
C {devices/lab_pin.sym} 1440 -1650 0 0 {name=p347 sig_type=std_logic lab=OUT+}
C {devices/lab_pin.sym} 1440 -1570 0 0 {name=p348 sig_type=std_logic lab=OUT-}
C {devices/lab_pin.sym} 1720 -1655 0 0 {name=p349 sig_type=std_logic lab=OUT+}
C {devices/lab_pin.sym} 1720 -1575 0 0 {name=p350 sig_type=std_logic lab=OUT-}
C {devices/lab_pin.sym} 2040 -1655 0 0 {name=p351 sig_type=std_logic lab=OUT+}
C {devices/lab_pin.sym} 2040 -1575 0 0 {name=p352 sig_type=std_logic lab=OUT-}
C {devices/lab_pin.sym} 2380 -1655 0 0 {name=p353 sig_type=std_logic lab=OUT+}
C {devices/lab_pin.sym} 2380 -1575 0 0 {name=p354 sig_type=std_logic lab=OUT-}
C {devices/lab_pin.sym} 2650 -1655 0 0 {name=p355 sig_type=std_logic lab=OUT+}
C {devices/lab_pin.sym} 2650 -1575 0 0 {name=p356 sig_type=std_logic lab=OUT-}
C {devices/lab_pin.sym} 2950 -1650 0 0 {name=p357 sig_type=std_logic lab=OUT+}
C {devices/lab_pin.sym} 2950 -1570 0 0 {name=p358 sig_type=std_logic lab=OUT-}
C {devices/lab_pin.sym} 3220 -1645 0 0 {name=p359 sig_type=std_logic lab=OUT+}
C {devices/lab_pin.sym} 3220 -1565 0 0 {name=p360 sig_type=std_logic lab=OUT-}
C {devices/lab_pin.sym} 1170 -1860 0 0 {name=p361 sig_type=std_logic lab=OUT+}
C {devices/lab_pin.sym} 1170 -1780 0 0 {name=p362 sig_type=std_logic lab=OUT-}
C {devices/lab_pin.sym} 1440 -1865 0 0 {name=p363 sig_type=std_logic lab=OUT+}
C {devices/lab_pin.sym} 1440 -1785 0 0 {name=p364 sig_type=std_logic lab=OUT-}
C {devices/lab_pin.sym} 2020 -1860 0 0 {name=p365 sig_type=std_logic lab=OUT+}
C {devices/lab_pin.sym} 2020 -1780 0 0 {name=p366 sig_type=std_logic lab=OUT-}
C {devices/lab_pin.sym} 2660 -1860 0 0 {name=p367 sig_type=std_logic lab=OUT+}
C {devices/lab_pin.sym} 2660 -1780 0 0 {name=p368 sig_type=std_logic lab=OUT-}
C {devices/lab_pin.sym} 2930 -1855 0 0 {name=p369 sig_type=std_logic lab=OUT+}
C {devices/lab_pin.sym} 2930 -1775 0 0 {name=p370 sig_type=std_logic lab=OUT-}
C {devices/lab_pin.sym} 3210 -1860 0 0 {name=p371 sig_type=std_logic lab=OUT+}
C {devices/lab_pin.sym} 3210 -1780 0 0 {name=p372 sig_type=std_logic lab=OUT-}
C {devices/lab_pin.sym} 1170 -2060 0 0 {name=p373 sig_type=std_logic lab=OUT+}
C {devices/lab_pin.sym} 1170 -1980 0 0 {name=p374 sig_type=std_logic lab=OUT-}
C {devices/lab_pin.sym} 1440 -2060 0 0 {name=p375 sig_type=std_logic lab=OUT+}
C {devices/lab_pin.sym} 1440 -1980 0 0 {name=p376 sig_type=std_logic lab=OUT-}
C {devices/lab_pin.sym} 2020 -2065 0 0 {name=p377 sig_type=std_logic lab=OUT+}
C {devices/lab_pin.sym} 2020 -1985 0 0 {name=p378 sig_type=std_logic lab=OUT-}
C {devices/lab_pin.sym} 2360 -2065 0 0 {name=p379 sig_type=std_logic lab=OUT+}
C {devices/lab_pin.sym} 2360 -1985 0 0 {name=p380 sig_type=std_logic lab=OUT-}
C {devices/lab_pin.sym} 2940 -2060 0 0 {name=p381 sig_type=std_logic lab=OUT+}
C {devices/lab_pin.sym} 2940 -1980 0 0 {name=p382 sig_type=std_logic lab=OUT-}
C {symbols/nfet_03v3.sym} 2885 -2375 0 0 {name=M11
L=0.5u
W=19.2u
nf=1
m=1
ad="'int((nf+1)/2) * W/nf * 0.18u'"
pd="'2*int((nf+1)/2) * (W/nf + 0.18u)'"
as="'int((nf+2)/2) * W/nf * 0.18u'"
ps="'2*int((nf+2)/2) * (W/nf + 0.18u)'"
nrd="'0.18u / W'" nrs="'0.18u / W'"
sa=0 sb=0 sd=0
model=nfet_03v3
spiceprefix=X
}
C {symbols/nfet_03v3.sym} 2885 -2275 0 0 {name=M12
L=0.5u
W=19.2u
nf=1
m=1
ad="'int((nf+1)/2) * W/nf * 0.18u'"
pd="'2*int((nf+1)/2) * (W/nf + 0.18u)'"
as="'int((nf+2)/2) * W/nf * 0.18u'"
ps="'2*int((nf+2)/2) * (W/nf + 0.18u)'"
nrd="'0.18u / W'" nrs="'0.18u / W'"
sa=0 sb=0 sd=0
model=nfet_03v3
spiceprefix=X
}
C {devices/lab_pin.sym} 2840 -2425 0 0 {name=p233 sig_type=std_logic lab=C32_U}
C {devices/lab_pin.sym} 2840 -2275 0 0 {name=p234 sig_type=std_logic lab=C32_D}
C {devices/vsource.sym} 2455 -2600 0 0 {name=V1 value=0}
C {devices/vsource.sym} 2515 -2600 0 0 {name=V2 value=3.3}
C {devices/gnd.sym} 2455 -2540 0 0 {name=l1 lab=GND}
C {devices/lab_wire.sym} 2455 -2650 0 0 {name=p264 sig_type=std_logic lab=VSS}
C {devices/lab_wire.sym} 2515 -2650 0 0 {name=p265 sig_type=std_logic lab=VDD}
C {devices/lab_wire.sym} 2515 -2550 0 0 {name=p266 sig_type=std_logic lab=VSS}
C {devices/isource.sym} 2675 -2600 0 0 {name=I1 value=80u}
C {devices/lab_wire.sym} 2675 -2660 0 0 {name=p267 sig_type=std_logic lab=VDD}
C {devices/lab_wire.sym} 2905 -2220 0 0 {name=p270 sig_type=std_logic lab=VSS}
C {devices/lab_wire.sym} 1835 -2680 0 0 {name=p271 sig_type=std_logic lab=VSS}
C {devices/lab_wire.sym} 1875 -2660 0 0 {name=p272 sig_type=std_logic lab=VSS}
C {devices/lab_wire.sym} 1915 -2640 0 0 {name=p273 sig_type=std_logic lab=VSS}
C {devices/lab_wire.sym} 1795 -2700 0 0 {name=p274 sig_type=std_logic lab=VSS}
C {devices/vsource.sym} 1755 -2770 0 0 {name=V13 value="pulse(0 3.3 0 10p 10p 6.4u 12.8u)"}
C {devices/lab_wire.sym} 1755 -2720 0 0 {name=p275 sig_type=std_logic lab=VSS}
C {devices/vsource.sym} 1715 -2790 0 0 {name=V14 value="pulse(0 3.3 0 10p 10p 3.2u 6.4u)"}
C {devices/lab_wire.sym} 1715 -2740 0 0 {name=p276 sig_type=std_logic lab=VSS}
C {devices/vsource.sym} 1795 -2750 0 0 {name=V9 value="pulse(0 3.3 0 10p 10p 12.8u 25.6u)"}
C {devices/vsource.sym} 1835 -2730 0 0 {name=V3 value="pulse(0 3.3 0 10p 10p 25.6u 51.2u)"}
C {devices/vsource.sym} 1875 -2710 0 0 {name=V4 value="pulse(0 3.3 0 10p 10p 51.2u 102.4u)"}
C {devices/vsource.sym} 1915 -2690 0 0 {name=V5 value="pulse(0 3.3 0 10p 10p 102.4u 204.8u)"}
C {devices/code_shown.sym} 2070 -2905 0 0 {name=MODELS only_toplevel=true
format="tcleval( @value )"
value="
.include $::180MCU_MODELS/design.ngspice
.lib $::180MCU_MODELS/sm141064.ngspice typical
"}
C {devices/code_shown.sym} 3080 -2915 0 1 {name=NGSPICE only_toplevel=true
value="
.options savecurrents
.control
*save all
op

tran tmax 205u
plot v(OUT+) v(OUT-)

*write DAC_12Bit_TB.raw
.endc
"}
C {devices/res.sym} 3310 -2485 0 0 {name=R1
value=200
footprint=1206
device=resistor
m=1}
C {devices/res.sym} 3160 -2465 0 0 {name=R2
value=200
footprint=1206
device=resistor
m=1}
C {devices/lab_wire.sym} 3160 -2405 0 0 {name=p268 sig_type=std_logic lab=VDD}
C {devices/lab_wire.sym} 3310 -2425 0 0 {name=p277 sig_type=std_logic lab=VDD}
C {devices/lab_pin.sym} 3030 -2515 0 0 {name=p231 sig_type=std_logic lab=OUT+}
C {devices/lab_pin.sym} 3055 -2495 0 0 {name=p232 sig_type=std_logic lab=OUT-}
